VERSION 5.7 ;
BUSBITCHARS "[]" ;
DIVIDERCHAR "/" ;

PROPERTYDEFINITIONS
  MACRO pkpIndependentSourceSHA256 STRING ;
  MACRO CatenaDesignType STRING ;
END PROPERTYDEFINITIONS

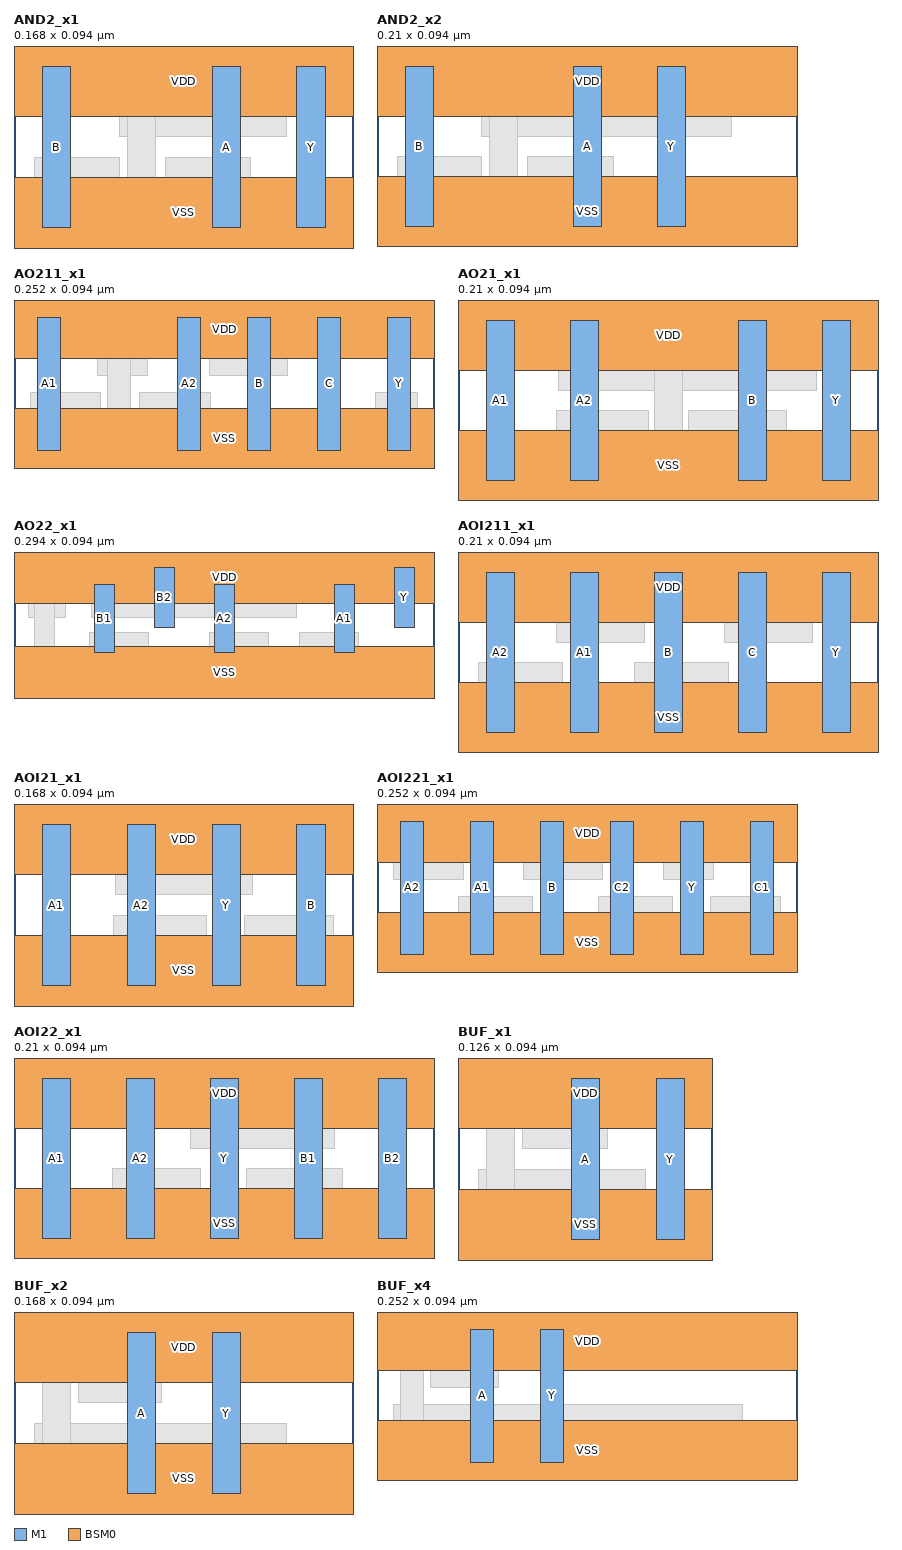
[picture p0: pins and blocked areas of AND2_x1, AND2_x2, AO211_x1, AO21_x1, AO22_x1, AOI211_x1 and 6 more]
MACRO AND2_x1
  CLASS CORE ;
  ORIGIN 0 0 ;
  FOREIGN AND2_x1 0 0 ;
  SIZE 0.168 BY 0.094 ;
  SYMMETRY X Y ;
  SITE CoreSite ;
  PIN A
    DIRECTION INPUT ;
    USE SIGNAL ;
    PORT
      LAYER M1 ;
        RECT 0.098 0.007 0.112 0.087 ;
    END
  END A
  PIN B
    DIRECTION INPUT ;
    USE SIGNAL ;
    PORT
      LAYER M1 ;
        RECT 0.014 0.007 0.028 0.087 ;
    END
  END B
  PIN Y
    DIRECTION OUTPUT ;
    USE SIGNAL ;
    PORT
      LAYER M1 ;
        RECT 0.14 0.007 0.154 0.087 ;
    END
  END Y
  PIN VDD
    DIRECTION INOUT ;
    USE POWER ;
    SHAPE ABUTMENT ;
    PORT
      LAYER BSM0 ;
        RECT 0 0.062 0.168 0.126 ;
    END
  END VDD
  PIN VSS
    DIRECTION INOUT ;
    USE GROUND ;
    SHAPE ABUTMENT ;
    PORT
      LAYER BSM0 ;
        RECT 0 -0.032 0.168 0.032 ;
    END
  END VSS
  OBS
    LAYER M0 ;
      RECT 0.133 0.01 0.158 0.021 ;
      RECT 0.133 0.073 0.158 0.084 ;
      RECT 0.052 0.052 0.135 0.063 ;
      RECT 0.075 0.031 0.117 0.042 ;
      RECT 0.01 0.01 0.08 0.021 ;
      RECT 0.05 0.073 0.08 0.084 ;
      RECT 0.01 0.031 0.052 0.042 ;
    LAYER M1 ;
      RECT 0.056 0.007 0.07 0.087 ;
  END
END AND2_x1

MACRO AND2_x2
  CLASS CORE ;
  ORIGIN 0 0 ;
  FOREIGN AND2_x2 0 0 ;
  SIZE 0.21 BY 0.094 ;
  SYMMETRY X Y ;
  SITE CoreSite ;
  PIN A
    DIRECTION INPUT ;
    USE SIGNAL ;
    PORT
      LAYER M1 ;
        RECT 0.098 0.007 0.112 0.087 ;
    END
  END A
  PIN B
    DIRECTION INPUT ;
    USE SIGNAL ;
    PORT
      LAYER M1 ;
        RECT 0.014 0.007 0.028 0.087 ;
    END
  END B
  PIN Y
    DIRECTION OUTPUT ;
    USE SIGNAL ;
    PORT
      LAYER M1 ;
        RECT 0.14 0.007 0.154 0.087 ;
    END
  END Y
  PIN VDD
    DIRECTION INOUT ;
    USE POWER ;
    SHAPE ABUTMENT ;
    PORT
      LAYER BSM0 ;
        RECT 0 0.062 0.21 0.126 ;
    END
  END VDD
  PIN VSS
    DIRECTION INOUT ;
    USE GROUND ;
    SHAPE ABUTMENT ;
    PORT
      LAYER BSM0 ;
        RECT 0 -0.032 0.21 0.032 ;
    END
  END VSS
  OBS
    LAYER M0 ;
      RECT 0.052 0.052 0.177 0.063 ;
      RECT 0.134 0.01 0.164 0.021 ;
      RECT 0.134 0.073 0.164 0.084 ;
      RECT 0.075 0.031 0.118 0.042 ;
      RECT 0.01 0.01 0.08 0.021 ;
      RECT 0.05 0.073 0.08 0.084 ;
      RECT 0.01 0.031 0.052 0.042 ;
    LAYER M1 ;
      RECT 0.056 0.007 0.07 0.087 ;
  END
END AND2_x2

MACRO AO211_x1
  CLASS CORE ;
  ORIGIN 0 0 ;
  FOREIGN AO211_x1 0 0 ;
  SIZE 0.252 BY 0.094 ;
  SYMMETRY X Y ;
  SITE CoreSite ;
  PIN A1
    DIRECTION INPUT ;
    USE SIGNAL ;
    PORT
      LAYER M1 ;
        RECT 0.014 0.007 0.028 0.087 ;
    END
  END A1
  PIN A2
    DIRECTION INPUT ;
    USE SIGNAL ;
    PORT
      LAYER M1 ;
        RECT 0.098 0.007 0.112 0.087 ;
    END
  END A2
  PIN B
    DIRECTION INPUT ;
    USE SIGNAL ;
    PORT
      LAYER M1 ;
        RECT 0.14 0.007 0.154 0.087 ;
    END
  END B
  PIN C
    DIRECTION INPUT ;
    USE SIGNAL ;
    PORT
      LAYER M1 ;
        RECT 0.182 0.007 0.196 0.087 ;
    END
  END C
  PIN Y
    DIRECTION OUTPUT ;
    USE SIGNAL ;
    PORT
      LAYER M1 ;
        RECT 0.224 0.007 0.238 0.087 ;
    END
  END Y
  PIN VDD
    DIRECTION INOUT ;
    USE POWER ;
    SHAPE ABUTMENT ;
    PORT
      LAYER BSM0 ;
        RECT 0 0.062 0.252 0.126 ;
    END
  END VDD
  PIN VSS
    DIRECTION INOUT ;
    USE GROUND ;
    SHAPE ABUTMENT ;
    PORT
      LAYER BSM0 ;
        RECT 0 -0.032 0.252 0.032 ;
    END
  END VSS
  OBS
    LAYER M0 ;
      RECT 0.217 0.031 0.242 0.042 ;
      RECT 0.217 0.073 0.242 0.084 ;
      RECT 0.01 0.01 0.219 0.021 ;
      RECT 0.159 0.073 0.199 0.084 ;
      RECT 0.117 0.052 0.164 0.063 ;
      RECT 0.075 0.031 0.118 0.042 ;
      RECT 0.012 0.073 0.114 0.084 ;
      RECT 0.05 0.052 0.08 0.063 ;
      RECT 0.01 0.031 0.052 0.042 ;
    LAYER M1 ;
      RECT 0.056 0.007 0.07 0.087 ;
  END
END AO211_x1

MACRO AO21_x1
  CLASS CORE ;
  ORIGIN 0 0 ;
  FOREIGN AO21_x1 0 0 ;
  SIZE 0.21 BY 0.094 ;
  SYMMETRY X Y ;
  SITE CoreSite ;
  PIN A1
    DIRECTION INPUT ;
    USE SIGNAL ;
    PORT
      LAYER M1 ;
        RECT 0.014 0.007 0.028 0.087 ;
    END
  END A1
  PIN A2
    DIRECTION INPUT ;
    USE SIGNAL ;
    PORT
      LAYER M1 ;
        RECT 0.056 0.007 0.07 0.087 ;
    END
  END A2
  PIN B
    DIRECTION INPUT ;
    USE SIGNAL ;
    PORT
      LAYER M1 ;
        RECT 0.14 0.007 0.154 0.087 ;
    END
  END B
  PIN Y
    DIRECTION OUTPUT ;
    USE SIGNAL ;
    PORT
      LAYER M1 ;
        RECT 0.182 0.007 0.196 0.087 ;
    END
  END Y
  PIN VDD
    DIRECTION INOUT ;
    USE POWER ;
    SHAPE ABUTMENT ;
    PORT
      LAYER BSM0 ;
        RECT 0 0.062 0.21 0.126 ;
    END
  END VDD
  PIN VSS
    DIRECTION INOUT ;
    USE GROUND ;
    SHAPE ABUTMENT ;
    PORT
      LAYER BSM0 ;
        RECT 0 -0.032 0.21 0.032 ;
    END
  END VSS
  OBS
    LAYER M0 ;
      RECT 0.172 0.01 0.2 0.021 ;
      RECT 0.172 0.073 0.2 0.084 ;
      RECT 0.05 0.052 0.179 0.063 ;
      RECT 0.115 0.031 0.164 0.042 ;
      RECT 0.088 0.01 0.119 0.021 ;
      RECT 0.01 0.073 0.117 0.084 ;
      RECT 0.049 0.031 0.095 0.042 ;
      RECT 0.01 0.01 0.053 0.021 ;
    LAYER M1 ;
      RECT 0.098 0.007 0.112 0.087 ;
  END
END AO21_x1

MACRO AO22_x1
  CLASS CORE ;
  ORIGIN 0 0 ;
  FOREIGN AO22_x1 0 0 ;
  SIZE 0.294 BY 0.094 ;
  SYMMETRY X Y ;
  SITE CoreSite ;
  PIN A1
    DIRECTION INPUT ;
    USE SIGNAL ;
    PORT
      LAYER M1 ;
        RECT 0.224 0.028 0.238 0.0755 ;
    END
  END A1
  PIN A2
    DIRECTION INPUT ;
    USE SIGNAL ;
    PORT
      LAYER M1 ;
        RECT 0.14 0.028 0.154 0.0755 ;
    END
  END A2
  PIN B1
    DIRECTION INPUT ;
    USE SIGNAL ;
    PORT
      LAYER M1 ;
        RECT 0.056 0.028 0.07 0.0755 ;
    END
  END B1
  PIN B2
    DIRECTION INPUT ;
    USE SIGNAL ;
    PORT
      LAYER M1 ;
        RECT 0.098 0.045 0.112 0.087 ;
    END
  END B2
  PIN Y
    DIRECTION OUTPUT ;
    USE SIGNAL ;
    PORT
      LAYER M1 ;
        RECT 0.266 0.045 0.28 0.087 ;
    END
  END Y
  PIN VDD
    DIRECTION INOUT ;
    USE POWER ;
    SHAPE ABUTMENT ;
    PORT
      LAYER BSM0 ;
        RECT 0 0.062 0.294 0.126 ;
    END
  END VDD
  PIN VSS
    DIRECTION INOUT ;
    USE GROUND ;
    SHAPE ABUTMENT ;
    PORT
      LAYER BSM0 ;
        RECT 0 -0.032 0.294 0.032 ;
    END
  END VSS
  OBS
    LAYER M0 ;
      RECT 0.256 0.073 0.284 0.084 ;
      RECT 0.01 0.01 0.262 0.021 ;
      RECT 0.2 0.031 0.241 0.042 ;
      RECT 0.054 0.052 0.198 0.063 ;
      RECT 0.137 0.031 0.178 0.042 ;
      RECT 0.032 0.073 0.115 0.084 ;
      RECT 0.053 0.031 0.094 0.042 ;
      RECT 0.01 0.052 0.036 0.063 ;
    LAYER M1 ;
      RECT 0.014 0.007 0.028 0.076 ;
  END
  PROPERTY pkpIndependentSourceSHA256 "be00ef7e564fc46890b79b18678042070a181a3fd22f0e1ad2fda87f76c24992" ;
END AO22_x1

MACRO AOI211_x1
  CLASS CORE ;
  ORIGIN 0 0 ;
  FOREIGN AOI211_x1 0 0 ;
  SIZE 0.21 BY 0.094 ;
  SYMMETRY X Y ;
  SITE CoreSite ;
  PIN A1
    DIRECTION INPUT ;
    USE SIGNAL ;
    PORT
      LAYER M1 ;
        RECT 0.056 0.007 0.07 0.087 ;
    END
  END A1
  PIN A2
    DIRECTION INPUT ;
    USE SIGNAL ;
    PORT
      LAYER M1 ;
        RECT 0.014 0.007 0.028 0.087 ;
    END
  END A2
  PIN B
    DIRECTION INPUT ;
    USE SIGNAL ;
    PORT
      LAYER M1 ;
        RECT 0.098 0.007 0.112 0.087 ;
    END
  END B
  PIN C
    DIRECTION INPUT ;
    USE SIGNAL ;
    PORT
      LAYER M1 ;
        RECT 0.14 0.007 0.154 0.087 ;
    END
  END C
  PIN Y
    DIRECTION OUTPUT ;
    USE SIGNAL ;
    PORT
      LAYER M1 ;
        RECT 0.182 0.007 0.196 0.087 ;
    END
  END Y
  PIN VDD
    DIRECTION INOUT ;
    USE POWER ;
    SHAPE ABUTMENT ;
    PORT
      LAYER BSM0 ;
        RECT 0 0.062 0.21 0.126 ;
    END
  END VDD
  PIN VSS
    DIRECTION INOUT ;
    USE GROUND ;
    SHAPE ABUTMENT ;
    PORT
      LAYER BSM0 ;
        RECT 0 -0.032 0.21 0.032 ;
    END
  END VSS
  OBS
    LAYER M0 ;
      RECT 0.096 0.01 0.2 0.021 ;
      RECT 0.172 0.073 0.2 0.084 ;
      RECT 0.133 0.052 0.177 0.063 ;
      RECT 0.088 0.031 0.135 0.042 ;
      RECT 0.012 0.073 0.114 0.084 ;
      RECT 0.049 0.052 0.093 0.063 ;
      RECT 0.01 0.031 0.052 0.042 ;
  END
END AOI211_x1

MACRO AOI21_x1
  CLASS CORE ;
  ORIGIN 0 0 ;
  FOREIGN AOI21_x1 0 0 ;
  SIZE 0.168 BY 0.094 ;
  SYMMETRY X Y ;
  SITE CoreSite ;
  PIN A1
    DIRECTION INPUT ;
    USE SIGNAL ;
    PORT
      LAYER M1 ;
        RECT 0.014 0.007 0.028 0.087 ;
    END
  END A1
  PIN A2
    DIRECTION INPUT ;
    USE SIGNAL ;
    PORT
      LAYER M1 ;
        RECT 0.056 0.007 0.07 0.087 ;
    END
  END A2
  PIN B
    DIRECTION INPUT ;
    USE SIGNAL ;
    PORT
      LAYER M1 ;
        RECT 0.14 0.007 0.154 0.087 ;
    END
  END B
  PIN Y
    DIRECTION OUTPUT ;
    USE SIGNAL ;
    PORT
      LAYER M1 ;
        RECT 0.098 0.007 0.112 0.087 ;
    END
  END Y
  PIN VDD
    DIRECTION INOUT ;
    USE POWER ;
    SHAPE ABUTMENT ;
    PORT
      LAYER BSM0 ;
        RECT 0 0.062 0.168 0.126 ;
    END
  END VDD
  PIN VSS
    DIRECTION INOUT ;
    USE GROUND ;
    SHAPE ABUTMENT ;
    PORT
      LAYER BSM0 ;
        RECT 0 -0.032 0.168 0.032 ;
    END
  END VSS
  OBS
    LAYER M0 ;
      RECT 0.114 0.031 0.158 0.042 ;
      RECT 0.088 0.01 0.118 0.021 ;
      RECT 0.05 0.052 0.118 0.063 ;
      RECT 0.01 0.073 0.118 0.084 ;
      RECT 0.049 0.031 0.095 0.042 ;
      RECT 0.01 0.01 0.052 0.021 ;
  END
END AOI21_x1

MACRO AOI221_x1
  CLASS CORE ;
  ORIGIN 0 0 ;
  FOREIGN AOI221_x1 0 0 ;
  SIZE 0.252 BY 0.094 ;
  SYMMETRY X Y ;
  SITE CoreSite ;
  PIN A1
    DIRECTION INPUT ;
    USE SIGNAL ;
    PORT
      LAYER M1 ;
        RECT 0.056 0.007 0.07 0.087 ;
    END
  END A1
  PIN A2
    DIRECTION INPUT ;
    USE SIGNAL ;
    PORT
      LAYER M1 ;
        RECT 0.014 0.007 0.028 0.087 ;
    END
  END A2
  PIN B
    DIRECTION INPUT ;
    USE SIGNAL ;
    PORT
      LAYER M1 ;
        RECT 0.098 0.007 0.112 0.087 ;
    END
  END B
  PIN C1
    DIRECTION INPUT ;
    USE SIGNAL ;
    PORT
      LAYER M1 ;
        RECT 0.224 0.007 0.238 0.087 ;
    END
  END C1
  PIN C2
    DIRECTION INPUT ;
    USE SIGNAL ;
    PORT
      LAYER M1 ;
        RECT 0.14 0.007 0.154 0.087 ;
    END
  END C2
  PIN Y
    DIRECTION OUTPUT ;
    USE SIGNAL ;
    PORT
      LAYER M1 ;
        RECT 0.182 0.007 0.196 0.087 ;
    END
  END Y
  PIN VDD
    DIRECTION INOUT ;
    USE POWER ;
    SHAPE ABUTMENT ;
    PORT
      LAYER BSM0 ;
        RECT 0 0.062 0.252 0.126 ;
    END
  END VDD
  PIN VSS
    DIRECTION INOUT ;
    USE GROUND ;
    SHAPE ABUTMENT ;
    PORT
      LAYER BSM0 ;
        RECT 0 -0.032 0.252 0.032 ;
    END
  END VSS
  OBS
    LAYER M0 ;
      RECT 0.2 0.031 0.242 0.042 ;
      RECT 0.096 0.01 0.24 0.021 ;
      RECT 0.138 0.073 0.24 0.084 ;
      RECT 0.172 0.052 0.202 0.063 ;
      RECT 0.133 0.031 0.177 0.042 ;
      RECT 0.088 0.052 0.135 0.063 ;
      RECT 0.012 0.073 0.114 0.084 ;
      RECT 0.049 0.031 0.093 0.042 ;
      RECT 0.01 0.052 0.052 0.063 ;
  END
END AOI221_x1

MACRO AOI22_x1
  CLASS CORE ;
  ORIGIN 0 0 ;
  FOREIGN AOI22_x1 0 0 ;
  SIZE 0.21 BY 0.094 ;
  SYMMETRY X Y ;
  SITE CoreSite ;
  PIN A1
    DIRECTION INPUT ;
    USE SIGNAL ;
    PORT
      LAYER M1 ;
        RECT 0.014 0.007 0.028 0.087 ;
    END
  END A1
  PIN A2
    DIRECTION INPUT ;
    USE SIGNAL ;
    PORT
      LAYER M1 ;
        RECT 0.056 0.007 0.07 0.087 ;
    END
  END A2
  PIN B1
    DIRECTION INPUT ;
    USE SIGNAL ;
    PORT
      LAYER M1 ;
        RECT 0.14 0.007 0.154 0.087 ;
    END
  END B1
  PIN B2
    DIRECTION INPUT ;
    USE SIGNAL ;
    PORT
      LAYER M1 ;
        RECT 0.182 0.007 0.196 0.087 ;
    END
  END B2
  PIN Y
    DIRECTION OUTPUT ;
    USE SIGNAL ;
    PORT
      LAYER M1 ;
        RECT 0.098 0.007 0.112 0.087 ;
    END
  END Y
  PIN VDD
    DIRECTION INOUT ;
    USE POWER ;
    SHAPE ABUTMENT ;
    PORT
      LAYER BSM0 ;
        RECT 0 0.062 0.21 0.126 ;
    END
  END VDD
  PIN VSS
    DIRECTION INOUT ;
    USE GROUND ;
    SHAPE ABUTMENT ;
    PORT
      LAYER BSM0 ;
        RECT 0 -0.032 0.21 0.032 ;
    END
  END VSS
  OBS
    LAYER M0 ;
      RECT 0.156 0.01 0.2 0.021 ;
      RECT 0.01 0.073 0.2 0.084 ;
      RECT 0.116 0.031 0.164 0.042 ;
      RECT 0.088 0.052 0.16 0.063 ;
      RECT 0.088 0.01 0.119 0.021 ;
      RECT 0.049 0.031 0.093 0.042 ;
      RECT 0.011 0.01 0.052 0.021 ;
  END
  PROPERTY CatenaDesignType "deviceLevel" ;
END AOI22_x1

MACRO BUF_x1
  CLASS CORE ;
  ORIGIN 0 0 ;
  FOREIGN BUF_x1 0 0 ;
  SIZE 0.126 BY 0.094 ;
  SYMMETRY X Y ;
  SITE CoreSite ;
  PIN A
    DIRECTION INPUT ;
    USE SIGNAL ;
    PORT
      LAYER M1 ;
        RECT 0.056 0.007 0.07 0.087 ;
    END
  END A
  PIN Y
    DIRECTION OUTPUT ;
    USE SIGNAL ;
    PORT
      LAYER M1 ;
        RECT 0.098 0.007 0.112 0.087 ;
    END
  END Y
  PIN VDD
    DIRECTION INOUT ;
    USE POWER ;
    SHAPE ABUTMENT ;
    PORT
      LAYER BSM0 ;
        RECT 0 0.062 0.126 0.126 ;
    END
  END VDD
  PIN VSS
    DIRECTION INOUT ;
    USE GROUND ;
    SHAPE ABUTMENT ;
    PORT
      LAYER BSM0 ;
        RECT 0 -0.032 0.126 0.032 ;
    END
  END VSS
  OBS
    LAYER M0 ;
      RECT 0.088 0.01 0.116 0.021 ;
      RECT 0.088 0.073 0.116 0.084 ;
      RECT 0.01 0.031 0.093 0.042 ;
      RECT 0.032 0.052 0.074 0.063 ;
      RECT 0.01 0.01 0.035 0.021 ;
      RECT 0.01 0.073 0.035 0.084 ;
    LAYER M1 ;
      RECT 0.014 0.007 0.028 0.087 ;
  END
END BUF_x1

MACRO BUF_x2
  CLASS CORE ;
  ORIGIN 0 0 ;
  FOREIGN BUF_x2 0 0 ;
  SIZE 0.168 BY 0.094 ;
  SYMMETRY X Y ;
  SITE CoreSite ;
  PIN A
    DIRECTION INPUT ;
    USE SIGNAL ;
    PORT
      LAYER M1 ;
        RECT 0.056 0.007 0.07 0.087 ;
    END
  END A
  PIN Y
    DIRECTION OUTPUT ;
    USE SIGNAL ;
    PORT
      LAYER M1 ;
        RECT 0.098 0.007 0.112 0.087 ;
    END
  END Y
  PIN VDD
    DIRECTION INOUT ;
    USE POWER ;
    SHAPE ABUTMENT ;
    PORT
      LAYER BSM0 ;
        RECT 0 0.062 0.168 0.126 ;
    END
  END VDD
  PIN VSS
    DIRECTION INOUT ;
    USE GROUND ;
    SHAPE ABUTMENT ;
    PORT
      LAYER BSM0 ;
        RECT 0 -0.032 0.168 0.032 ;
    END
  END VSS
  OBS
    LAYER M0 ;
      RECT 0.01 0.031 0.135 0.042 ;
      RECT 0.088 0.01 0.118 0.021 ;
      RECT 0.088 0.073 0.118 0.084 ;
      RECT 0.032 0.052 0.073 0.063 ;
      RECT 0.01 0.01 0.035 0.021 ;
      RECT 0.01 0.073 0.035 0.084 ;
    LAYER M1 ;
      RECT 0.014 0.007 0.028 0.087 ;
  END
END BUF_x2

MACRO BUF_x4
  CLASS CORE ;
  ORIGIN 0 0 ;
  FOREIGN BUF_x4 0 0 ;
  SIZE 0.252 BY 0.094 ;
  SYMMETRY X Y ;
  SITE CoreSite ;
  PIN A
    DIRECTION INPUT ;
    USE SIGNAL ;
    PORT
      LAYER M1 ;
        RECT 0.056 0.007 0.07 0.087 ;
    END
  END A
  PIN Y
    DIRECTION OUTPUT ;
    USE SIGNAL ;
    PORT
      LAYER M1 ;
        RECT 0.098 0.007 0.112 0.087 ;
    END
  END Y
  PIN VDD
    DIRECTION INOUT ;
    USE POWER ;
    SHAPE ABUTMENT ;
    PORT
      LAYER BSM0 ;
        RECT 0 0.062 0.252 0.126 ;
    END
  END VDD
  PIN VSS
    DIRECTION INOUT ;
    USE GROUND ;
    SHAPE ABUTMENT ;
    PORT
      LAYER BSM0 ;
        RECT 0 -0.032 0.252 0.032 ;
    END
  END VSS
  OBS
    LAYER M0 ;
      RECT 0.01 0.031 0.219 0.042 ;
      RECT 0.092 0.01 0.199 0.021 ;
      RECT 0.092 0.073 0.199 0.084 ;
      RECT 0.032 0.052 0.073 0.063 ;
      RECT 0.01 0.01 0.035 0.021 ;
      RECT 0.01 0.073 0.035 0.084 ;
    LAYER M1 ;
      RECT 0.014 0.007 0.028 0.087 ;
  END
END BUF_x4

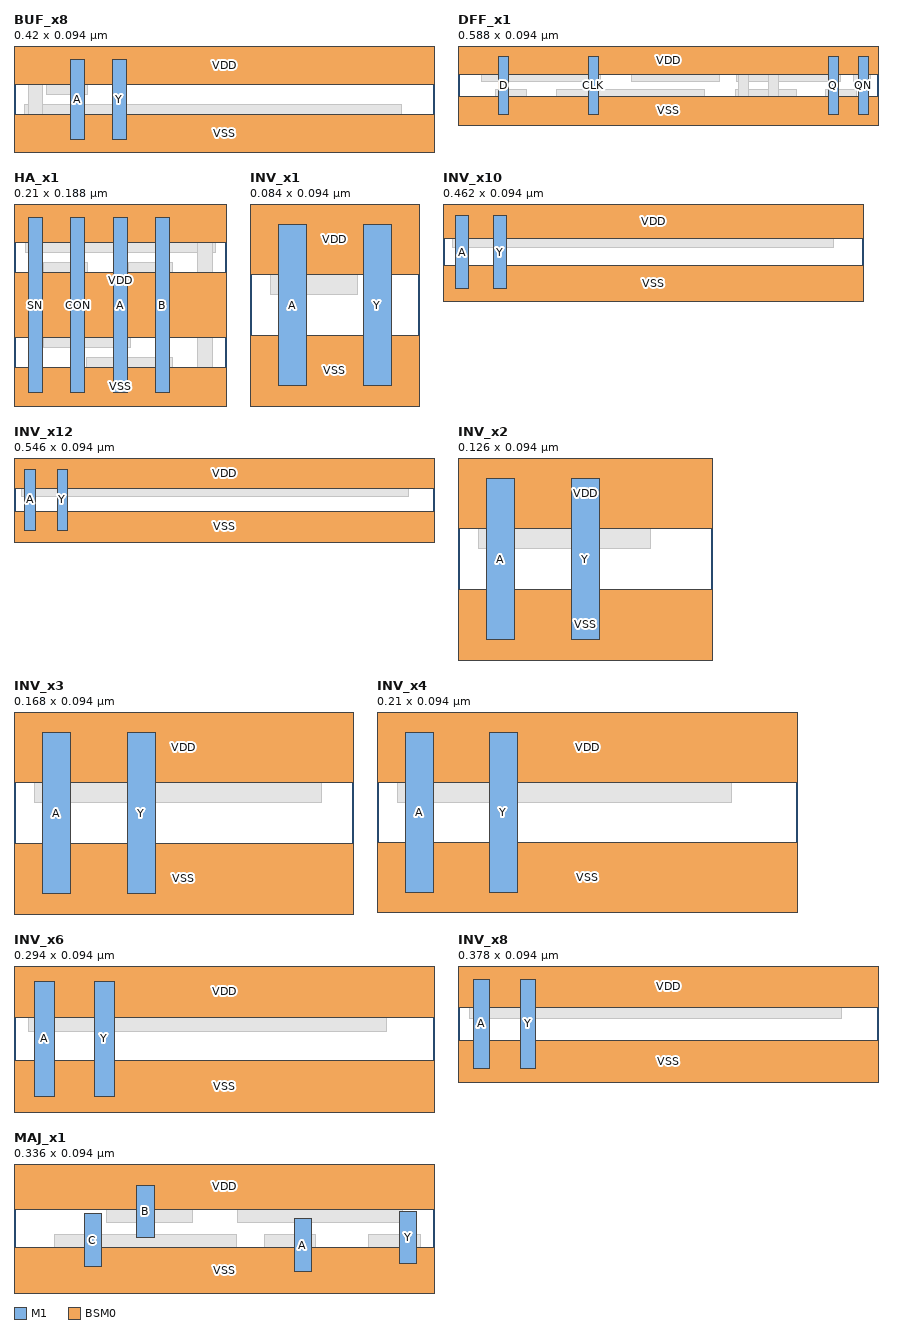
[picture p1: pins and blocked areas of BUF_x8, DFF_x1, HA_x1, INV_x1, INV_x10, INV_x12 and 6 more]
MACRO BUF_x8
  CLASS CORE ;
  ORIGIN 0 0 ;
  FOREIGN BUF_x8 0 0 ;
  SIZE 0.42 BY 0.094 ;
  SYMMETRY X Y ;
  SITE CoreSite ;
  PIN A
    DIRECTION INPUT ;
    USE SIGNAL ;
    PORT
      LAYER M1 ;
        RECT 0.056 0.007 0.07 0.087 ;
    END
  END A
  PIN Y
    DIRECTION OUTPUT ;
    USE SIGNAL ;
    PORT
      LAYER M1 ;
        RECT 0.098 0.007 0.112 0.087 ;
    END
  END Y
  PIN VDD
    DIRECTION INOUT ;
    USE POWER ;
    SHAPE ABUTMENT ;
    PORT
      LAYER BSM0 ;
        RECT 0 0.062 0.42 0.126 ;
    END
  END VDD
  PIN VSS
    DIRECTION INOUT ;
    USE GROUND ;
    SHAPE ABUTMENT ;
    PORT
      LAYER BSM0 ;
        RECT 0 -0.032 0.42 0.032 ;
    END
  END VSS
  OBS
    LAYER M0 ;
      RECT 0.01 0.031 0.387 0.042 ;
      RECT 0.092 0.01 0.367 0.021 ;
      RECT 0.092 0.073 0.367 0.084 ;
      RECT 0.032 0.052 0.073 0.063 ;
      RECT 0.01 0.01 0.035 0.021 ;
      RECT 0.01 0.073 0.035 0.084 ;
    LAYER M1 ;
      RECT 0.014 0.007 0.028 0.087 ;
  END
END BUF_x8

MACRO DFF_x1
  CLASS CORE ;
  ORIGIN 0 0 ;
  FOREIGN DFF_x1 0 0 ;
  SIZE 0.588 BY 0.094 ;
  SYMMETRY X Y ;
  SITE CoreSite ;
  PIN CLK
    DIRECTION INPUT ;
    USE CLOCK ;
    PORT
      LAYER M1 ;
        RECT 0.182 0.007 0.196 0.087 ;
    END
  END CLK
  PIN D
    DIRECTION INPUT ;
    USE SIGNAL ;
    PORT
      LAYER M1 ;
        RECT 0.056 0.007 0.07 0.087 ;
    END
  END D
  PIN Q
    DIRECTION OUTPUT ;
    USE SIGNAL ;
    PORT
      LAYER M1 ;
        RECT 0.518 0.007 0.532 0.087 ;
    END
  END Q
  PIN QN
    DIRECTION OUTPUT ;
    USE SIGNAL ;
    PORT
      LAYER M1 ;
        RECT 0.56 0.007 0.574 0.087 ;
    END
  END QN
  PIN VDD
    DIRECTION INOUT ;
    USE POWER ;
    SHAPE ABUTMENT ;
    PORT
      LAYER BSM0 ;
        RECT 0 0.062 0.588 0.126 ;
    END
  END VDD
  PIN VSS
    DIRECTION INOUT ;
    USE GROUND ;
    SHAPE ABUTMENT ;
    PORT
      LAYER BSM0 ;
        RECT 0 -0.032 0.588 0.032 ;
    END
  END VSS
  OBS
    LAYER M0 ;
      RECT 0.553 0.052 0.578 0.063 ;
      RECT 0.495 0.01 0.577 0.021 ;
      RECT 0.515 0.031 0.5585 0.042 ;
      RECT 0.39 0.052 0.535 0.063 ;
      RECT 0.389 0.031 0.4745 0.042 ;
      RECT 0.431 0.073 0.4745 0.084 ;
      RECT 0.179 0.01 0.451 0.021 ;
      RECT 0.012 0.073 0.409 0.084 ;
      RECT 0.243 0.052 0.366 0.063 ;
      RECT 0.138 0.031 0.345 0.042 ;
      RECT 0.033 0.052 0.199 0.063 ;
      RECT 0.012 0.01 0.135 0.021 ;
      RECT 0.053 0.031 0.0965 0.042 ;
    LAYER M1 ;
      RECT 0.434 0.007 0.448 0.087 ;
      RECT 0.392 0.007 0.406 0.087 ;
  END
END DFF_x1

MACRO HA_x1
  CLASS CORE ;
  ORIGIN 0 0 ;
  FOREIGN HA_x1 0 0 ;
  SIZE 0.21 BY 0.188 ;
  SYMMETRY X Y ;
  SITE CoreSite ;
  PIN A
    DIRECTION INPUT ;
    USE SIGNAL ;
    PORT
      LAYER M1 ;
        RECT 0.098 0.007 0.112 0.181 ;
    END
  END A
  PIN B
    DIRECTION INPUT ;
    USE SIGNAL ;
    PORT
      LAYER M1 ;
        RECT 0.14 0.007 0.154 0.181 ;
    END
  END B
  PIN CON
    DIRECTION OUTPUT ;
    USE SIGNAL ;
    PORT
      LAYER M1 ;
        RECT 0.056 0.007 0.07 0.181 ;
    END
  END CON
  PIN SN
    DIRECTION OUTPUT ;
    USE SIGNAL ;
    PORT
      LAYER M1 ;
        RECT 0.014 0.007 0.028 0.181 ;
    END
  END SN
  PIN VDD
    DIRECTION INOUT ;
    USE POWER ;
    SHAPE ABUTMENT ;
    PORT
      LAYER BSM0 ;
        RECT 0 0.062 0.21 0.126 ;
    END
  END VDD
  PIN VSS
    DIRECTION INOUT ;
    USE GROUND ;
    SHAPE ABUTMENT ;
    PORT
      LAYER BSM0 ;
        RECT 0 -0.032 0.21 0.032 ;
        RECT 0 0.156 0.21 0.22 ;
    END
  END VSS
  OBS
    LAYER M0 ;
      RECT 0.1345 0.104 0.199 0.115 ;
      RECT 0.011 0.146 0.199 0.157 ;
      RECT 0.0715 0.031 0.157 0.042 ;
      RECT 0.1135 0.125 0.157 0.136 ;
      RECT 0.054 0.167 0.156 0.178 ;
      RECT 0.053 0.01 0.1175 0.021 ;
      RECT 0.0295 0.052 0.115 0.063 ;
      RECT 0.0715 0.104 0.115 0.115 ;
      RECT 0.012 0.073 0.114 0.084 ;
      RECT 0.0295 0.125 0.073 0.136 ;
      RECT 0.01 0.104 0.035 0.115 ;
    LAYER M1 ;
      RECT 0.182 0.007 0.196 0.181 ;
  END
END HA_x1

MACRO INV_x1
  CLASS CORE ;
  ORIGIN 0 0 ;
  FOREIGN INV_x1 0 0 ;
  SIZE 0.084 BY 0.094 ;
  SYMMETRY X Y ;
  SITE CoreSite ;
  PIN A
    DIRECTION INPUT ;
    USE SIGNAL ;
    PORT
      LAYER M1 ;
        RECT 0.014 0.007 0.028 0.087 ;
    END
  END A
  PIN Y
    DIRECTION OUTPUT ;
    USE SIGNAL ;
    PORT
      LAYER M1 ;
        RECT 0.056 0.007 0.07 0.087 ;
    END
  END Y
  PIN VDD
    DIRECTION INOUT ;
    USE POWER ;
    SHAPE ABUTMENT ;
    PORT
      LAYER BSM0 ;
        RECT 0 0.062 0.084 0.126 ;
    END
  END VDD
  PIN VSS
    DIRECTION INOUT ;
    USE GROUND ;
    SHAPE ABUTMENT ;
    PORT
      LAYER BSM0 ;
        RECT 0 -0.032 0.084 0.032 ;
    END
  END VSS
  OBS
    LAYER M0 ;
      RECT 0.032 0.01 0.074 0.021 ;
      RECT 0.032 0.073 0.074 0.084 ;
      RECT 0.01 0.052 0.053 0.063 ;
  END
END INV_x1

MACRO INV_x10
  CLASS CORE ;
  ORIGIN 0 0 ;
  FOREIGN INV_x10 0 0 ;
  SIZE 0.462 BY 0.094 ;
  SYMMETRY X Y ;
  SITE CoreSite ;
  PIN A
    DIRECTION INPUT ;
    USE SIGNAL ;
    PORT
      LAYER M1 ;
        RECT 0.014 0.007 0.028 0.087 ;
    END
  END A
  PIN Y
    DIRECTION OUTPUT ;
    USE SIGNAL ;
    PORT
      LAYER M1 ;
        RECT 0.056 0.007 0.07 0.087 ;
    END
  END Y
  PIN VDD
    DIRECTION INOUT ;
    USE POWER ;
    SHAPE ABUTMENT ;
    PORT
      LAYER BSM0 ;
        RECT 0 0.062 0.462 0.126 ;
    END
  END VDD
  PIN VSS
    DIRECTION INOUT ;
    USE GROUND ;
    SHAPE ABUTMENT ;
    PORT
      LAYER BSM0 ;
        RECT 0 -0.032 0.462 0.032 ;
    END
  END VSS
  OBS
    LAYER M0 ;
      RECT 0.01 0.052 0.429 0.063 ;
      RECT 0.05 0.01 0.41 0.021 ;
      RECT 0.05 0.073 0.409 0.084 ;
  END
END INV_x10

MACRO INV_x12
  CLASS CORE ;
  ORIGIN 0 0 ;
  FOREIGN INV_x12 0 0 ;
  SIZE 0.546 BY 0.094 ;
  SYMMETRY X Y ;
  SITE CoreSite ;
  PIN A
    DIRECTION INPUT ;
    USE SIGNAL ;
    PORT
      LAYER M1 ;
        RECT 0.014 0.007 0.028 0.087 ;
    END
  END A
  PIN Y
    DIRECTION OUTPUT ;
    USE SIGNAL ;
    PORT
      LAYER M1 ;
        RECT 0.056 0.007 0.07 0.087 ;
    END
  END Y
  PIN VDD
    DIRECTION INOUT ;
    USE POWER ;
    SHAPE ABUTMENT ;
    PORT
      LAYER BSM0 ;
        RECT 0 0.062 0.546 0.126 ;
    END
  END VDD
  PIN VSS
    DIRECTION INOUT ;
    USE GROUND ;
    SHAPE ABUTMENT ;
    PORT
      LAYER BSM0 ;
        RECT 0 -0.032 0.546 0.032 ;
    END
  END VSS
  OBS
    LAYER M0 ;
      RECT 0.01 0.052 0.513 0.063 ;
      RECT 0.05 0.01 0.493 0.021 ;
      RECT 0.05 0.073 0.493 0.084 ;
  END
END INV_x12

MACRO INV_x2
  CLASS CORE ;
  ORIGIN 0 0 ;
  FOREIGN INV_x2 0 0 ;
  SIZE 0.126 BY 0.094 ;
  SYMMETRY X Y ;
  SITE CoreSite ;
  PIN A
    DIRECTION INPUT ;
    USE SIGNAL ;
    PORT
      LAYER M1 ;
        RECT 0.014 0.007 0.028 0.087 ;
    END
  END A
  PIN Y
    DIRECTION OUTPUT ;
    USE SIGNAL ;
    PORT
      LAYER M1 ;
        RECT 0.056 0.007 0.07 0.087 ;
    END
  END Y
  PIN VDD
    DIRECTION INOUT ;
    USE POWER ;
    SHAPE ABUTMENT ;
    PORT
      LAYER BSM0 ;
        RECT 0 0.062 0.126 0.126 ;
    END
  END VDD
  PIN VSS
    DIRECTION INOUT ;
    USE GROUND ;
    SHAPE ABUTMENT ;
    PORT
      LAYER BSM0 ;
        RECT 0 -0.032 0.126 0.032 ;
    END
  END VSS
  OBS
    LAYER M0 ;
      RECT 0.01 0.052 0.095 0.063 ;
      RECT 0.05 0.01 0.08 0.021 ;
      RECT 0.05 0.073 0.08 0.084 ;
  END
END INV_x2

MACRO INV_x3
  CLASS CORE ;
  ORIGIN 0 0 ;
  FOREIGN INV_x3 0 0 ;
  SIZE 0.168 BY 0.094 ;
  SYMMETRY X Y ;
  SITE CoreSite ;
  PIN A
    DIRECTION INPUT ;
    USE SIGNAL ;
    PORT
      LAYER M1 ;
        RECT 0.014 0.007 0.028 0.087 ;
    END
  END A
  PIN Y
    DIRECTION OUTPUT ;
    USE SIGNAL ;
    PORT
      LAYER M1 ;
        RECT 0.056 0.007 0.07 0.087 ;
    END
  END Y
  PIN VDD
    DIRECTION INOUT ;
    USE POWER ;
    SHAPE ABUTMENT ;
    PORT
      LAYER BSM0 ;
        RECT 0 0.062 0.168 0.126 ;
    END
  END VDD
  PIN VSS
    DIRECTION INOUT ;
    USE GROUND ;
    SHAPE ABUTMENT ;
    PORT
      LAYER BSM0 ;
        RECT 0 -0.032 0.168 0.032 ;
    END
  END VSS
  OBS
    LAYER M0 ;
      RECT 0.05 0.01 0.157 0.021 ;
      RECT 0.05 0.073 0.157 0.084 ;
      RECT 0.01 0.052 0.152 0.063 ;
  END
END INV_x3

MACRO INV_x4
  CLASS CORE ;
  ORIGIN 0 0 ;
  FOREIGN INV_x4 0 0 ;
  SIZE 0.21 BY 0.094 ;
  SYMMETRY X Y ;
  SITE CoreSite ;
  PIN A
    DIRECTION INPUT ;
    USE SIGNAL ;
    PORT
      LAYER M1 ;
        RECT 0.014 0.007 0.028 0.087 ;
    END
  END A
  PIN Y
    DIRECTION OUTPUT ;
    USE SIGNAL ;
    PORT
      LAYER M1 ;
        RECT 0.056 0.007 0.07 0.087 ;
    END
  END Y
  PIN VDD
    DIRECTION INOUT ;
    USE POWER ;
    SHAPE ABUTMENT ;
    PORT
      LAYER BSM0 ;
        RECT 0 0.062 0.21 0.126 ;
    END
  END VDD
  PIN VSS
    DIRECTION INOUT ;
    USE GROUND ;
    SHAPE ABUTMENT ;
    PORT
      LAYER BSM0 ;
        RECT 0 -0.032 0.21 0.032 ;
    END
  END VSS
  OBS
    LAYER M0 ;
      RECT 0.01 0.052 0.177 0.063 ;
      RECT 0.05 0.01 0.157 0.021 ;
      RECT 0.05 0.073 0.157 0.084 ;
  END
END INV_x4

MACRO INV_x6
  CLASS CORE ;
  ORIGIN 0 0 ;
  FOREIGN INV_x6 0 0 ;
  SIZE 0.294 BY 0.094 ;
  SYMMETRY X Y ;
  SITE CoreSite ;
  PIN A
    DIRECTION INPUT ;
    USE SIGNAL ;
    PORT
      LAYER M1 ;
        RECT 0.014 0.007 0.028 0.087 ;
    END
  END A
  PIN Y
    DIRECTION OUTPUT ;
    USE SIGNAL ;
    PORT
      LAYER M1 ;
        RECT 0.056 0.007 0.07 0.087 ;
    END
  END Y
  PIN VDD
    DIRECTION INOUT ;
    USE POWER ;
    SHAPE ABUTMENT ;
    PORT
      LAYER BSM0 ;
        RECT 0 0.062 0.294 0.126 ;
    END
  END VDD
  PIN VSS
    DIRECTION INOUT ;
    USE GROUND ;
    SHAPE ABUTMENT ;
    PORT
      LAYER BSM0 ;
        RECT 0 -0.032 0.294 0.032 ;
    END
  END VSS
  OBS
    LAYER M0 ;
      RECT 0.01 0.052 0.261 0.063 ;
      RECT 0.05 0.01 0.241 0.021 ;
      RECT 0.05 0.073 0.241 0.084 ;
  END
END INV_x6

MACRO INV_x8
  CLASS CORE ;
  ORIGIN 0 0 ;
  FOREIGN INV_x8 0 0 ;
  SIZE 0.378 BY 0.094 ;
  SYMMETRY X Y ;
  SITE CoreSite ;
  PIN A
    DIRECTION INPUT ;
    USE SIGNAL ;
    PORT
      LAYER M1 ;
        RECT 0.014 0.007 0.028 0.087 ;
    END
  END A
  PIN Y
    DIRECTION OUTPUT ;
    USE SIGNAL ;
    PORT
      LAYER M1 ;
        RECT 0.056 0.007 0.07 0.087 ;
    END
  END Y
  PIN VDD
    DIRECTION INOUT ;
    USE POWER ;
    SHAPE ABUTMENT ;
    PORT
      LAYER BSM0 ;
        RECT 0 0.062 0.378 0.126 ;
    END
  END VDD
  PIN VSS
    DIRECTION INOUT ;
    USE GROUND ;
    SHAPE ABUTMENT ;
    PORT
      LAYER BSM0 ;
        RECT 0 -0.032 0.378 0.032 ;
    END
  END VSS
  OBS
    LAYER M0 ;
      RECT 0.01 0.052 0.345 0.063 ;
      RECT 0.05 0.01 0.325 0.021 ;
      RECT 0.05 0.073 0.325 0.084 ;
  END
END INV_x8

MACRO MAJ_x1
  CLASS CORE ;
  ORIGIN 0 0 ;
  FOREIGN MAJ_x1 0 0 ;
  SIZE 0.336 BY 0.094 ;
  SYMMETRY X Y ;
  SITE CoreSite ;
  PIN A
    DIRECTION INPUT ;
    USE SIGNAL ;
    PORT
      LAYER M1 ;
        RECT 0.224 0.0125 0.238 0.0545 ;
    END
  END A
  PIN B
    DIRECTION INPUT ;
    USE SIGNAL ;
    PORT
      LAYER M1 ;
        RECT 0.098 0.0395 0.112 0.0815 ;
    END
  END B
  PIN C
    DIRECTION INPUT ;
    USE SIGNAL ;
    PORT
      LAYER M1 ;
        RECT 0.056 0.0165 0.07 0.0585 ;
    END
  END C
  PIN Y
    DIRECTION OUTPUT ;
    USE SIGNAL ;
    PORT
      LAYER M1 ;
        RECT 0.308 0.0185 0.322 0.0605 ;
    END
  END Y
  PIN VDD
    DIRECTION INOUT ;
    USE POWER ;
    SHAPE ABUTMENT ;
    PORT
      LAYER BSM0 ;
        RECT 0 0.062 0.336 0.126 ;
    END
  END VDD
  PIN VSS
    DIRECTION INOUT ;
    USE GROUND ;
    SHAPE ABUTMENT ;
    PORT
      LAYER BSM0 ;
        RECT 0 -0.032 0.336 0.032 ;
    END
  END VSS
  OBS
    LAYER M0 ;
      RECT 0.284 0.031 0.325 0.042 ;
      RECT 0.179 0.052 0.311 0.063 ;
      RECT 0.053 0.073 0.255 0.084 ;
      RECT 0.053 0.01 0.241 0.021 ;
      RECT 0.2 0.031 0.241 0.042 ;
      RECT 0.032 0.031 0.178 0.042 ;
      RECT 0.074 0.052 0.143 0.063 ;
  END
  PROPERTY pkpIndependentSourceSHA256 "c6524f313f9f278eef24616a36d5740bf9d2db56e62a49f5a092eda3790d412a" ;
END MAJ_x1

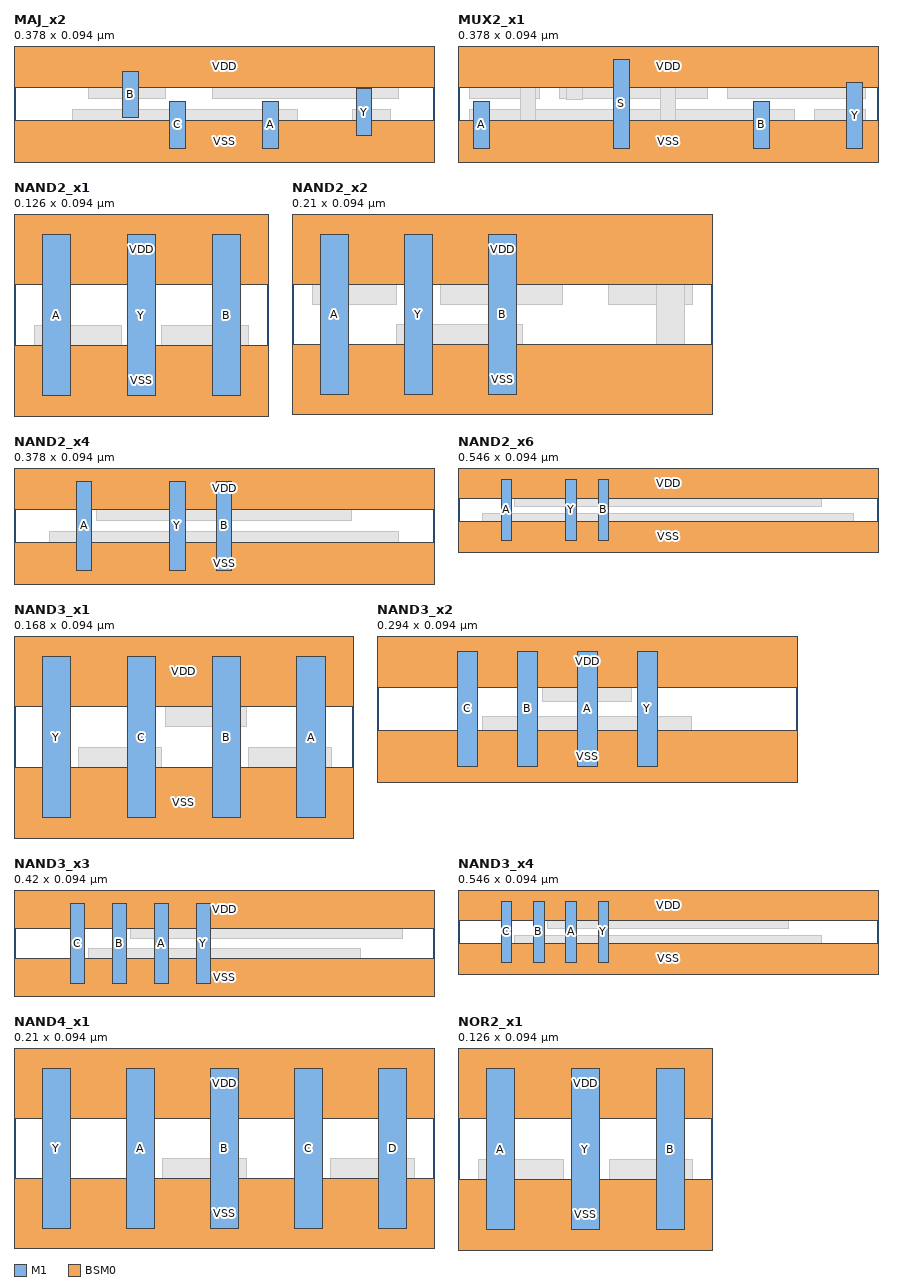
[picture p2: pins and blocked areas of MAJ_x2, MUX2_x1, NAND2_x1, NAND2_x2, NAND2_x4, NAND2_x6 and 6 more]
MACRO MAJ_x2
  CLASS CORE ;
  ORIGIN 0 0 ;
  FOREIGN MAJ_x2 0 0 ;
  SIZE 0.378 BY 0.094 ;
  SYMMETRY X Y ;
  SITE CoreSite ;
  PIN A
    DIRECTION INPUT ;
    USE SIGNAL ;
    PORT
      LAYER M1 ;
        RECT 0.224 0.007 0.238 0.049 ;
    END
  END A
  PIN B
    DIRECTION INPUT ;
    USE SIGNAL ;
    PORT
      LAYER M1 ;
        RECT 0.098 0.0345 0.112 0.0765 ;
    END
  END B
  PIN C
    DIRECTION INPUT ;
    USE SIGNAL ;
    PORT
      LAYER M1 ;
        RECT 0.14 0.007 0.154 0.049 ;
    END
  END C
  PIN Y
    DIRECTION OUTPUT ;
    USE SIGNAL ;
    PORT
      LAYER M1 ;
        RECT 0.308 0.0185 0.322 0.0605 ;
    END
  END Y
  PIN VDD
    DIRECTION INOUT ;
    USE POWER ;
    SHAPE ABUTMENT ;
    PORT
      LAYER BSM0 ;
        RECT 0 0.062 0.378 0.126 ;
    END
  END VDD
  PIN VSS
    DIRECTION INOUT ;
    USE GROUND ;
    SHAPE ABUTMENT ;
    PORT
      LAYER BSM0 ;
        RECT 0 -0.032 0.378 0.032 ;
    END
  END VSS
  OBS
    LAYER M0 ;
      RECT 0.179 0.052 0.346 0.063 ;
      RECT 0.305 0.031 0.339 0.042 ;
      RECT 0.053 0.031 0.255 0.042 ;
      RECT 0.2 0.01 0.241 0.021 ;
      RECT 0.053 0.073 0.241 0.084 ;
      RECT 0.032 0.01 0.178 0.021 ;
      RECT 0.067 0.052 0.136 0.063 ;
  END
  PROPERTY pkpIndependentSourceSHA256 "503b818806f41a63dad2466f29618c257b77dd42f9f3fecf4337ea01a5ae6336" ;
END MAJ_x2

MACRO MUX2_x1
  CLASS CORE ;
  ORIGIN 0 0 ;
  FOREIGN MUX2_x1 0 0 ;
  SIZE 0.378 BY 0.094 ;
  SYMMETRY X Y ;
  SITE CoreSite ;
  PIN A
    DIRECTION INPUT ;
    USE SIGNAL ;
    PORT
      LAYER M1 ;
        RECT 0.014 0.007 0.028 0.049 ;
    END
  END A
  PIN B
    DIRECTION INPUT ;
    USE SIGNAL ;
    PORT
      LAYER M1 ;
        RECT 0.266 0.007 0.28 0.049 ;
    END
  END B
  PIN S
    DIRECTION INPUT ;
    USE SIGNAL ;
    PORT
      LAYER M1 ;
        RECT 0.14 0.007 0.154 0.087 ;
    END
  END S
  PIN Y
    DIRECTION OUTPUT ;
    USE SIGNAL ;
    PORT
      LAYER M1 ;
        RECT 0.35 0.007 0.364 0.066 ;
    END
  END Y
  PIN VDD
    DIRECTION INOUT ;
    USE POWER ;
    SHAPE ABUTMENT ;
    PORT
      LAYER BSM0 ;
        RECT 0 0.062 0.378 0.126 ;
    END
  END VDD
  PIN VSS
    DIRECTION INOUT ;
    USE GROUND ;
    SHAPE ABUTMENT ;
    PORT
      LAYER BSM0 ;
        RECT 0 -0.032 0.378 0.032 ;
    END
  END VSS
  OBS
    LAYER M0 ;
      RECT 0.321 0.031 0.367 0.042 ;
      RECT 0.2425 0.052 0.367 0.063 ;
      RECT 0.174 0.073 0.346 0.084 ;
      RECT 0.243 0.01 0.3035 0.021 ;
      RECT 0.01 0.031 0.303 0.042 ;
      RECT 0.175 0.01 0.225 0.021 ;
      RECT 0.091 0.052 0.2245 0.063 ;
      RECT 0.111 0.01 0.157 0.021 ;
      RECT 0.033 0.073 0.156 0.084 ;
      RECT 0.01 0.01 0.093 0.021 ;
      RECT 0.01 0.052 0.073 0.063 ;
    LAYER M1 ;
      RECT 0.182 0.007 0.196 0.087 ;
      RECT 0.098 0.051 0.112 0.087 ;
      RECT 0.056 0.007 0.07 0.066 ;
  END
END MUX2_x1

MACRO NAND2_x1
  CLASS CORE ;
  ORIGIN 0 0 ;
  FOREIGN NAND2_x1 0 0 ;
  SIZE 0.126 BY 0.094 ;
  SYMMETRY X Y ;
  SITE CoreSite ;
  PIN A
    DIRECTION INPUT ;
    USE SIGNAL ;
    PORT
      LAYER M1 ;
        RECT 0.014 0.007 0.028 0.087 ;
    END
  END A
  PIN B
    DIRECTION INPUT ;
    USE SIGNAL ;
    PORT
      LAYER M1 ;
        RECT 0.098 0.007 0.112 0.087 ;
    END
  END B
  PIN Y
    DIRECTION OUTPUT ;
    USE SIGNAL ;
    PORT
      LAYER M1 ;
        RECT 0.056 0.007 0.07 0.087 ;
    END
  END Y
  PIN VDD
    DIRECTION INOUT ;
    USE POWER ;
    SHAPE ABUTMENT ;
    PORT
      LAYER BSM0 ;
        RECT 0 0.062 0.126 0.126 ;
    END
  END VDD
  PIN VSS
    DIRECTION INOUT ;
    USE GROUND ;
    SHAPE ABUTMENT ;
    PORT
      LAYER BSM0 ;
        RECT 0 -0.032 0.126 0.032 ;
    END
  END VSS
  OBS
    LAYER M0 ;
      RECT 0.052 0.01 0.116 0.021 ;
      RECT 0.073 0.031 0.116 0.042 ;
      RECT 0.01 0.073 0.116 0.084 ;
      RECT 0.01 0.031 0.053 0.042 ;
  END
END NAND2_x1

MACRO NAND2_x2
  CLASS CORE ;
  ORIGIN 0 0 ;
  FOREIGN NAND2_x2 0 0 ;
  SIZE 0.21 BY 0.094 ;
  SYMMETRY X Y ;
  SITE CoreSite ;
  PIN A
    DIRECTION INPUT ;
    USE SIGNAL ;
    PORT
      LAYER M1 ;
        RECT 0.014 0.007 0.028 0.087 ;
    END
  END A
  PIN B
    DIRECTION INPUT ;
    USE SIGNAL ;
    PORT
      LAYER M1 ;
        RECT 0.098 0.007 0.112 0.087 ;
    END
  END B
  PIN Y
    DIRECTION OUTPUT ;
    USE SIGNAL ;
    PORT
      LAYER M1 ;
        RECT 0.056 0.007 0.07 0.087 ;
    END
  END Y
  PIN VDD
    DIRECTION INOUT ;
    USE POWER ;
    SHAPE ABUTMENT ;
    PORT
      LAYER BSM0 ;
        RECT 0 0.062 0.21 0.126 ;
    END
  END VDD
  PIN VSS
    DIRECTION INOUT ;
    USE GROUND ;
    SHAPE ABUTMENT ;
    PORT
      LAYER BSM0 ;
        RECT 0 -0.032 0.21 0.032 ;
    END
  END VSS
  OBS
    LAYER M0 ;
      RECT 0.01 0.01 0.2 0.021 ;
      RECT 0.158 0.052 0.2 0.063 ;
      RECT 0.01 0.073 0.199 0.084 ;
      RECT 0.074 0.052 0.135 0.063 ;
      RECT 0.052 0.031 0.115 0.042 ;
      RECT 0.01 0.052 0.052 0.063 ;
    LAYER M1 ;
      RECT 0.182 0.007 0.196 0.087 ;
  END
END NAND2_x2

MACRO NAND2_x4
  CLASS CORE ;
  ORIGIN 0 0 ;
  FOREIGN NAND2_x4 0 0 ;
  SIZE 0.378 BY 0.094 ;
  SYMMETRY X Y ;
  SITE CoreSite ;
  PIN A
    DIRECTION INPUT ;
    USE SIGNAL ;
    PORT
      LAYER M1 ;
        RECT 0.056 0.007 0.07 0.087 ;
    END
  END A
  PIN B
    DIRECTION INPUT ;
    USE SIGNAL ;
    PORT
      LAYER M1 ;
        RECT 0.182 0.007 0.196 0.087 ;
    END
  END B
  PIN Y
    DIRECTION OUTPUT ;
    USE SIGNAL ;
    PORT
      LAYER M1 ;
        RECT 0.14 0.007 0.154 0.087 ;
    END
  END Y
  PIN VDD
    DIRECTION INOUT ;
    USE POWER ;
    SHAPE ABUTMENT ;
    PORT
      LAYER BSM0 ;
        RECT 0 0.062 0.378 0.126 ;
    END
  END VDD
  PIN VSS
    DIRECTION INOUT ;
    USE GROUND ;
    SHAPE ABUTMENT ;
    PORT
      LAYER BSM0 ;
        RECT 0 -0.032 0.378 0.032 ;
    END
  END VSS
  OBS
    LAYER M0 ;
      RECT 0.01 0.073 0.368 0.084 ;
      RECT 0.032 0.031 0.346 0.042 ;
      RECT 0.074 0.052 0.304 0.063 ;
      RECT 0.094 0.01 0.284 0.021 ;
  END
END NAND2_x4

MACRO NAND2_x6
  CLASS CORE ;
  ORIGIN 0 0 ;
  FOREIGN NAND2_x6 0 0 ;
  SIZE 0.546 BY 0.094 ;
  SYMMETRY X Y ;
  SITE CoreSite ;
  PIN A
    DIRECTION INPUT ;
    USE SIGNAL ;
    PORT
      LAYER M1 ;
        RECT 0.056 0.007 0.07 0.087 ;
    END
  END A
  PIN B
    DIRECTION INPUT ;
    USE SIGNAL ;
    PORT
      LAYER M1 ;
        RECT 0.182 0.007 0.196 0.087 ;
    END
  END B
  PIN Y
    DIRECTION OUTPUT ;
    USE SIGNAL ;
    PORT
      LAYER M1 ;
        RECT 0.14 0.007 0.154 0.087 ;
    END
  END Y
  PIN VDD
    DIRECTION INOUT ;
    USE POWER ;
    SHAPE ABUTMENT ;
    PORT
      LAYER BSM0 ;
        RECT 0 0.062 0.546 0.126 ;
    END
  END VDD
  PIN VSS
    DIRECTION INOUT ;
    USE GROUND ;
    SHAPE ABUTMENT ;
    PORT
      LAYER BSM0 ;
        RECT 0 -0.032 0.546 0.032 ;
    END
  END VSS
  OBS
    LAYER M0 ;
      RECT 0.01 0.073 0.536 0.084 ;
      RECT 0.032 0.031 0.514 0.042 ;
      RECT 0.074 0.052 0.472 0.063 ;
      RECT 0.094 0.01 0.452 0.021 ;
  END
END NAND2_x6

MACRO NAND3_x1
  CLASS CORE ;
  ORIGIN 0 0 ;
  FOREIGN NAND3_x1 0 0 ;
  SIZE 0.168 BY 0.094 ;
  SYMMETRY X Y ;
  SITE CoreSite ;
  PIN A
    DIRECTION INPUT ;
    USE SIGNAL ;
    PORT
      LAYER M1 ;
        RECT 0.14 0.007 0.154 0.087 ;
    END
  END A
  PIN B
    DIRECTION INPUT ;
    USE SIGNAL ;
    PORT
      LAYER M1 ;
        RECT 0.098 0.007 0.112 0.087 ;
    END
  END B
  PIN C
    DIRECTION INPUT ;
    USE SIGNAL ;
    PORT
      LAYER M1 ;
        RECT 0.056 0.007 0.07 0.087 ;
    END
  END C
  PIN Y
    DIRECTION OUTPUT ;
    USE SIGNAL ;
    PORT
      LAYER M1 ;
        RECT 0.014 0.007 0.028 0.087 ;
    END
  END Y
  PIN VDD
    DIRECTION INOUT ;
    USE POWER ;
    SHAPE ABUTMENT ;
    PORT
      LAYER BSM0 ;
        RECT 0 0.062 0.168 0.126 ;
    END
  END VDD
  PIN VSS
    DIRECTION INOUT ;
    USE GROUND ;
    SHAPE ABUTMENT ;
    PORT
      LAYER BSM0 ;
        RECT 0 -0.032 0.168 0.032 ;
    END
  END VSS
  OBS
    LAYER M0 ;
      RECT 0.116 0.031 0.157 0.042 ;
      RECT 0.075 0.052 0.115 0.063 ;
      RECT 0.01 0.073 0.114 0.084 ;
      RECT 0.032 0.031 0.073 0.042 ;
  END
END NAND3_x1

MACRO NAND3_x2
  CLASS CORE ;
  ORIGIN 0 0 ;
  FOREIGN NAND3_x2 0 0 ;
  SIZE 0.294 BY 0.094 ;
  SYMMETRY X Y ;
  SITE CoreSite ;
  PIN A
    DIRECTION INPUT ;
    USE SIGNAL ;
    PORT
      LAYER M1 ;
        RECT 0.14 0.007 0.154 0.087 ;
    END
  END A
  PIN B
    DIRECTION INPUT ;
    USE SIGNAL ;
    PORT
      LAYER M1 ;
        RECT 0.098 0.007 0.112 0.087 ;
    END
  END B
  PIN C
    DIRECTION INPUT ;
    USE SIGNAL ;
    PORT
      LAYER M1 ;
        RECT 0.056 0.007 0.07 0.087 ;
    END
  END C
  PIN Y
    DIRECTION OUTPUT ;
    USE SIGNAL ;
    PORT
      LAYER M1 ;
        RECT 0.182 0.007 0.196 0.087 ;
    END
  END Y
  PIN VDD
    DIRECTION INOUT ;
    USE POWER ;
    SHAPE ABUTMENT ;
    PORT
      LAYER BSM0 ;
        RECT 0 0.062 0.294 0.126 ;
    END
  END VDD
  PIN VSS
    DIRECTION INOUT ;
    USE GROUND ;
    SHAPE ABUTMENT ;
    PORT
      LAYER BSM0 ;
        RECT 0 -0.032 0.294 0.032 ;
    END
  END VSS
  OBS
    LAYER M0 ;
      RECT 0.01 0.073 0.284 0.084 ;
      RECT 0.032 0.01 0.262 0.021 ;
      RECT 0.074 0.031 0.22 0.042 ;
      RECT 0.116 0.052 0.178 0.063 ;
  END
END NAND3_x2

MACRO NAND3_x3
  CLASS CORE ;
  ORIGIN 0 0 ;
  FOREIGN NAND3_x3 0 0 ;
  SIZE 0.42 BY 0.094 ;
  SYMMETRY X Y ;
  SITE CoreSite ;
  PIN A
    DIRECTION INPUT ;
    USE SIGNAL ;
    PORT
      LAYER M1 ;
        RECT 0.14 0.007 0.154 0.087 ;
    END
  END A
  PIN B
    DIRECTION INPUT ;
    USE SIGNAL ;
    PORT
      LAYER M1 ;
        RECT 0.098 0.007 0.112 0.087 ;
    END
  END B
  PIN C
    DIRECTION INPUT ;
    USE SIGNAL ;
    PORT
      LAYER M1 ;
        RECT 0.056 0.007 0.07 0.087 ;
    END
  END C
  PIN Y
    DIRECTION OUTPUT ;
    USE SIGNAL ;
    PORT
      LAYER M1 ;
        RECT 0.182 0.007 0.196 0.087 ;
    END
  END Y
  PIN VDD
    DIRECTION INOUT ;
    USE POWER ;
    SHAPE ABUTMENT ;
    PORT
      LAYER BSM0 ;
        RECT 0 0.062 0.42 0.126 ;
    END
  END VDD
  PIN VSS
    DIRECTION INOUT ;
    USE GROUND ;
    SHAPE ABUTMENT ;
    PORT
      LAYER BSM0 ;
        RECT 0 -0.032 0.42 0.032 ;
    END
  END VSS
  OBS
    LAYER M0 ;
      RECT 0.01 0.073 0.41 0.084 ;
      RECT 0.116 0.052 0.388 0.063 ;
      RECT 0.074 0.031 0.346 0.042 ;
      RECT 0.032 0.01 0.304 0.021 ;
  END
END NAND3_x3

MACRO NAND3_x4
  CLASS CORE ;
  ORIGIN 0 0 ;
  FOREIGN NAND3_x4 0 0 ;
  SIZE 0.546 BY 0.094 ;
  SYMMETRY X Y ;
  SITE CoreSite ;
  PIN A
    DIRECTION INPUT ;
    USE SIGNAL ;
    PORT
      LAYER M1 ;
        RECT 0.14 0.007 0.154 0.087 ;
    END
  END A
  PIN B
    DIRECTION INPUT ;
    USE SIGNAL ;
    PORT
      LAYER M1 ;
        RECT 0.098 0.007 0.112 0.087 ;
    END
  END B
  PIN C
    DIRECTION INPUT ;
    USE SIGNAL ;
    PORT
      LAYER M1 ;
        RECT 0.056 0.007 0.07 0.087 ;
    END
  END C
  PIN Y
    DIRECTION OUTPUT ;
    USE SIGNAL ;
    PORT
      LAYER M1 ;
        RECT 0.182 0.007 0.196 0.087 ;
    END
  END Y
  PIN VDD
    DIRECTION INOUT ;
    USE POWER ;
    SHAPE ABUTMENT ;
    PORT
      LAYER BSM0 ;
        RECT 0 0.062 0.546 0.126 ;
    END
  END VDD
  PIN VSS
    DIRECTION INOUT ;
    USE GROUND ;
    SHAPE ABUTMENT ;
    PORT
      LAYER BSM0 ;
        RECT 0 -0.032 0.546 0.032 ;
    END
  END VSS
  OBS
    LAYER M0 ;
      RECT 0.01 0.073 0.536 0.084 ;
      RECT 0.032 0.01 0.514 0.021 ;
      RECT 0.074 0.031 0.472 0.042 ;
      RECT 0.116 0.052 0.43 0.063 ;
  END
END NAND3_x4

MACRO NAND4_x1
  CLASS CORE ;
  ORIGIN 0 0 ;
  FOREIGN NAND4_x1 0 0 ;
  SIZE 0.21 BY 0.094 ;
  SYMMETRY X Y ;
  SITE CoreSite ;
  PIN A
    DIRECTION INPUT ;
    USE SIGNAL ;
    PORT
      LAYER M1 ;
        RECT 0.056 0.007 0.07 0.087 ;
    END
  END A
  PIN B
    DIRECTION INPUT ;
    USE SIGNAL ;
    PORT
      LAYER M1 ;
        RECT 0.098 0.007 0.112 0.087 ;
    END
  END B
  PIN C
    DIRECTION INPUT ;
    USE SIGNAL ;
    PORT
      LAYER M1 ;
        RECT 0.14 0.007 0.154 0.087 ;
    END
  END C
  PIN D
    DIRECTION INPUT ;
    USE SIGNAL ;
    PORT
      LAYER M1 ;
        RECT 0.182 0.007 0.196 0.087 ;
    END
  END D
  PIN Y
    DIRECTION OUTPUT ;
    USE SIGNAL ;
    PORT
      LAYER M1 ;
        RECT 0.014 0.007 0.028 0.087 ;
    END
  END Y
  PIN VDD
    DIRECTION INOUT ;
    USE POWER ;
    SHAPE ABUTMENT ;
    PORT
      LAYER BSM0 ;
        RECT 0 0.062 0.21 0.126 ;
    END
  END VDD
  PIN VSS
    DIRECTION INOUT ;
    USE GROUND ;
    SHAPE ABUTMENT ;
    PORT
      LAYER BSM0 ;
        RECT 0 -0.032 0.21 0.032 ;
    END
  END VSS
  OBS
    LAYER M0 ;
      RECT 0.158 0.031 0.2 0.042 ;
      RECT 0.01 0.073 0.2 0.084 ;
      RECT 0.116 0.01 0.158 0.021 ;
      RECT 0.074 0.031 0.116 0.042 ;
      RECT 0.032 0.01 0.074 0.021 ;
  END
END NAND4_x1

MACRO NOR2_x1
  CLASS CORE ;
  ORIGIN 0 0 ;
  FOREIGN NOR2_x1 0 0 ;
  SIZE 0.126 BY 0.094 ;
  SYMMETRY X Y ;
  SITE CoreSite ;
  PIN A
    DIRECTION INPUT ;
    USE SIGNAL ;
    PORT
      LAYER M1 ;
        RECT 0.014 0.007 0.028 0.087 ;
    END
  END A
  PIN B
    DIRECTION INPUT ;
    USE SIGNAL ;
    PORT
      LAYER M1 ;
        RECT 0.098 0.007 0.112 0.087 ;
    END
  END B
  PIN Y
    DIRECTION OUTPUT ;
    USE SIGNAL ;
    PORT
      LAYER M1 ;
        RECT 0.056 0.007 0.07 0.087 ;
    END
  END Y
  PIN VDD
    DIRECTION INOUT ;
    USE POWER ;
    SHAPE ABUTMENT ;
    PORT
      LAYER BSM0 ;
        RECT 0 0.062 0.126 0.126 ;
    END
  END VDD
  PIN VSS
    DIRECTION INOUT ;
    USE GROUND ;
    SHAPE ABUTMENT ;
    PORT
      LAYER BSM0 ;
        RECT 0 -0.032 0.126 0.032 ;
    END
  END VSS
  OBS
    LAYER M0 ;
      RECT 0.01 0.01 0.116 0.021 ;
      RECT 0.075 0.031 0.116 0.042 ;
      RECT 0.052 0.073 0.116 0.084 ;
      RECT 0.01 0.031 0.052 0.042 ;
  END
END NOR2_x1

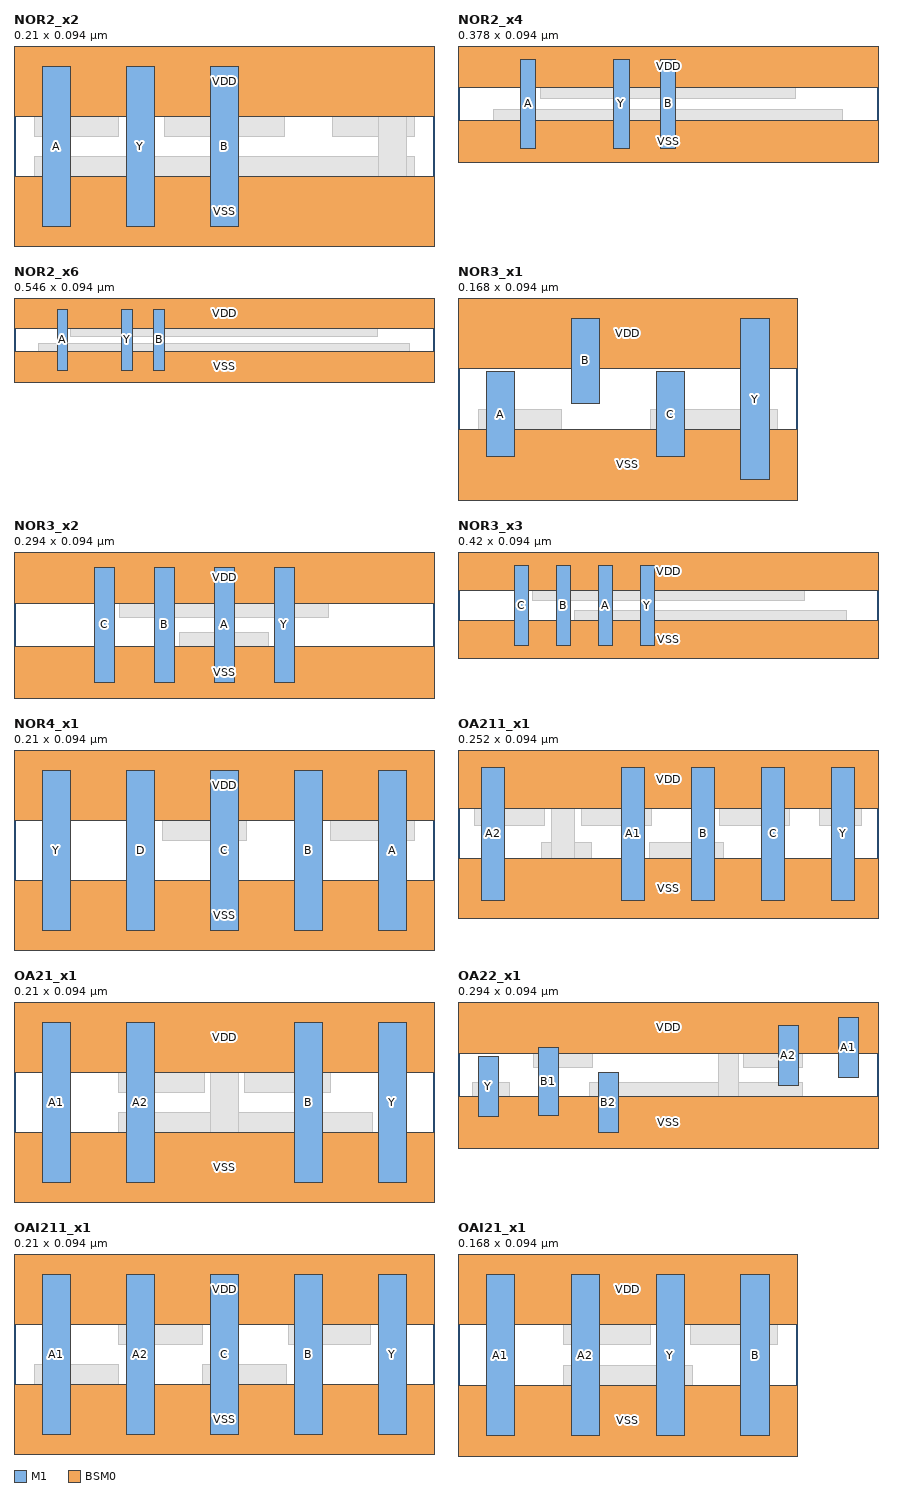
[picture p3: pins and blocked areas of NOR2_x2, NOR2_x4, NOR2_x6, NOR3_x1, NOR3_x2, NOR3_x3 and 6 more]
MACRO NOR2_x2
  CLASS CORE ;
  ORIGIN 0 0 ;
  FOREIGN NOR2_x2 0 0 ;
  SIZE 0.21 BY 0.094 ;
  SYMMETRY X Y ;
  SITE CoreSite ;
  PIN A
    DIRECTION INPUT ;
    USE SIGNAL ;
    PORT
      LAYER M1 ;
        RECT 0.014 0.007 0.028 0.087 ;
    END
  END A
  PIN B
    DIRECTION INPUT ;
    USE SIGNAL ;
    PORT
      LAYER M1 ;
        RECT 0.098 0.007 0.112 0.087 ;
    END
  END B
  PIN Y
    DIRECTION OUTPUT ;
    USE SIGNAL ;
    PORT
      LAYER M1 ;
        RECT 0.056 0.007 0.07 0.087 ;
    END
  END Y
  PIN VDD
    DIRECTION INOUT ;
    USE POWER ;
    SHAPE ABUTMENT ;
    PORT
      LAYER BSM0 ;
        RECT 0 0.062 0.21 0.126 ;
    END
  END VDD
  PIN VSS
    DIRECTION INOUT ;
    USE GROUND ;
    SHAPE ABUTMENT ;
    PORT
      LAYER BSM0 ;
        RECT 0 -0.032 0.21 0.032 ;
    END
  END VSS
  OBS
    LAYER M0 ;
      RECT 0.01 0.01 0.2 0.021 ;
      RECT 0.01 0.031 0.2 0.042 ;
      RECT 0.159 0.052 0.2 0.063 ;
      RECT 0.075 0.052 0.135 0.063 ;
      RECT 0.052 0.073 0.116 0.084 ;
      RECT 0.01 0.052 0.052 0.063 ;
    LAYER M1 ;
      RECT 0.182 0.007 0.196 0.087 ;
  END
END NOR2_x2

MACRO NOR2_x4
  CLASS CORE ;
  ORIGIN 0 0 ;
  FOREIGN NOR2_x4 0 0 ;
  SIZE 0.378 BY 0.094 ;
  SYMMETRY X Y ;
  SITE CoreSite ;
  PIN A
    DIRECTION INPUT ;
    USE SIGNAL ;
    PORT
      LAYER M1 ;
        RECT 0.056 0.007 0.07 0.087 ;
    END
  END A
  PIN B
    DIRECTION INPUT ;
    USE SIGNAL ;
    PORT
      LAYER M1 ;
        RECT 0.182 0.007 0.196 0.087 ;
    END
  END B
  PIN Y
    DIRECTION OUTPUT ;
    USE SIGNAL ;
    PORT
      LAYER M1 ;
        RECT 0.14 0.007 0.154 0.087 ;
    END
  END Y
  PIN VDD
    DIRECTION INOUT ;
    USE POWER ;
    SHAPE ABUTMENT ;
    PORT
      LAYER BSM0 ;
        RECT 0 0.062 0.378 0.126 ;
    END
  END VDD
  PIN VSS
    DIRECTION INOUT ;
    USE GROUND ;
    SHAPE ABUTMENT ;
    PORT
      LAYER BSM0 ;
        RECT 0 -0.032 0.378 0.032 ;
    END
  END VSS
  OBS
    LAYER M0 ;
      RECT 0.01 0.01 0.368 0.021 ;
      RECT 0.032 0.031 0.346 0.042 ;
      RECT 0.074 0.052 0.304 0.063 ;
      RECT 0.094 0.073 0.284 0.084 ;
  END
END NOR2_x4

MACRO NOR2_x6
  CLASS CORE ;
  ORIGIN 0 0 ;
  FOREIGN NOR2_x6 0 0 ;
  SIZE 0.546 BY 0.094 ;
  SYMMETRY X Y ;
  SITE CoreSite ;
  PIN A
    DIRECTION INPUT ;
    USE SIGNAL ;
    PORT
      LAYER M1 ;
        RECT 0.056 0.007 0.07 0.087 ;
    END
  END A
  PIN B
    DIRECTION INPUT ;
    USE SIGNAL ;
    PORT
      LAYER M1 ;
        RECT 0.182 0.007 0.196 0.087 ;
    END
  END B
  PIN Y
    DIRECTION OUTPUT ;
    USE SIGNAL ;
    PORT
      LAYER M1 ;
        RECT 0.14 0.007 0.154 0.087 ;
    END
  END Y
  PIN VDD
    DIRECTION INOUT ;
    USE POWER ;
    SHAPE ABUTMENT ;
    PORT
      LAYER BSM0 ;
        RECT 0 0.062 0.546 0.126 ;
    END
  END VDD
  PIN VSS
    DIRECTION INOUT ;
    USE GROUND ;
    SHAPE ABUTMENT ;
    PORT
      LAYER BSM0 ;
        RECT 0 -0.032 0.546 0.032 ;
    END
  END VSS
  OBS
    LAYER M0 ;
      RECT 0.01 0.01 0.536 0.021 ;
      RECT 0.032 0.031 0.514 0.042 ;
      RECT 0.074 0.052 0.472 0.063 ;
      RECT 0.094 0.073 0.452 0.084 ;
  END
END NOR2_x6

MACRO NOR3_x1
  CLASS CORE ;
  ORIGIN 0 0 ;
  FOREIGN NOR3_x1 0 0 ;
  SIZE 0.168 BY 0.094 ;
  SYMMETRY X Y ;
  SITE CoreSite ;
  PIN A
    DIRECTION INPUT ;
    USE SIGNAL ;
    PORT
      LAYER M1 ;
        RECT 0.014 0.0185 0.028 0.0605 ;
    END
  END A
  PIN B
    DIRECTION INPUT ;
    USE SIGNAL ;
    PORT
      LAYER M1 ;
        RECT 0.056 0.045 0.07 0.087 ;
    END
  END B
  PIN C
    DIRECTION INPUT ;
    USE SIGNAL ;
    PORT
      LAYER M1 ;
        RECT 0.098 0.0185 0.112 0.0605 ;
    END
  END C
  PIN Y
    DIRECTION OUTPUT ;
    USE SIGNAL ;
    PORT
      LAYER M1 ;
        RECT 0.14 0.007 0.154 0.087 ;
    END
  END Y
  PIN VDD
    DIRECTION INOUT ;
    USE POWER ;
    SHAPE ABUTMENT ;
    PORT
      LAYER BSM0 ;
        RECT 0 0.062 0.168 0.126 ;
    END
  END VDD
  PIN VSS
    DIRECTION INOUT ;
    USE GROUND ;
    SHAPE ABUTMENT ;
    PORT
      LAYER BSM0 ;
        RECT 0 -0.032 0.168 0.032 ;
    END
  END VSS
  OBS
    LAYER M0 ;
      RECT 0.095 0.031 0.158 0.042 ;
      RECT 0.012 0.01 0.157 0.021 ;
      RECT 0.116 0.073 0.157 0.084 ;
      RECT 0.053 0.073 0.0965 0.084 ;
      RECT 0.01 0.031 0.051 0.042 ;
  END
END NOR3_x1

MACRO NOR3_x2
  CLASS CORE ;
  ORIGIN 0 0 ;
  FOREIGN NOR3_x2 0 0 ;
  SIZE 0.294 BY 0.094 ;
  SYMMETRY X Y ;
  SITE CoreSite ;
  PIN A
    DIRECTION INPUT ;
    USE SIGNAL ;
    PORT
      LAYER M1 ;
        RECT 0.14 0.007 0.154 0.087 ;
    END
  END A
  PIN B
    DIRECTION INPUT ;
    USE SIGNAL ;
    PORT
      LAYER M1 ;
        RECT 0.098 0.007 0.112 0.087 ;
    END
  END B
  PIN C
    DIRECTION INPUT ;
    USE SIGNAL ;
    PORT
      LAYER M1 ;
        RECT 0.056 0.007 0.07 0.087 ;
    END
  END C
  PIN Y
    DIRECTION OUTPUT ;
    USE SIGNAL ;
    PORT
      LAYER M1 ;
        RECT 0.182 0.007 0.196 0.087 ;
    END
  END Y
  PIN VDD
    DIRECTION INOUT ;
    USE POWER ;
    SHAPE ABUTMENT ;
    PORT
      LAYER BSM0 ;
        RECT 0 0.062 0.294 0.126 ;
    END
  END VDD
  PIN VSS
    DIRECTION INOUT ;
    USE GROUND ;
    SHAPE ABUTMENT ;
    PORT
      LAYER BSM0 ;
        RECT 0 -0.032 0.294 0.032 ;
    END
  END VSS
  OBS
    LAYER M0 ;
      RECT 0.01 0.01 0.284 0.021 ;
      RECT 0.032 0.073 0.262 0.084 ;
      RECT 0.074 0.052 0.22 0.063 ;
      RECT 0.116 0.031 0.178 0.042 ;
  END
END NOR3_x2

MACRO NOR3_x3
  CLASS CORE ;
  ORIGIN 0 0 ;
  FOREIGN NOR3_x3 0 0 ;
  SIZE 0.42 BY 0.094 ;
  SYMMETRY X Y ;
  SITE CoreSite ;
  PIN A
    DIRECTION INPUT ;
    USE SIGNAL ;
    PORT
      LAYER M1 ;
        RECT 0.14 0.007 0.154 0.087 ;
    END
  END A
  PIN B
    DIRECTION INPUT ;
    USE SIGNAL ;
    PORT
      LAYER M1 ;
        RECT 0.098 0.007 0.112 0.087 ;
    END
  END B
  PIN C
    DIRECTION INPUT ;
    USE SIGNAL ;
    PORT
      LAYER M1 ;
        RECT 0.056 0.007 0.07 0.087 ;
    END
  END C
  PIN Y
    DIRECTION OUTPUT ;
    USE SIGNAL ;
    PORT
      LAYER M1 ;
        RECT 0.182 0.007 0.196 0.087 ;
    END
  END Y
  PIN VDD
    DIRECTION INOUT ;
    USE POWER ;
    SHAPE ABUTMENT ;
    PORT
      LAYER BSM0 ;
        RECT 0 0.062 0.42 0.126 ;
    END
  END VDD
  PIN VSS
    DIRECTION INOUT ;
    USE GROUND ;
    SHAPE ABUTMENT ;
    PORT
      LAYER BSM0 ;
        RECT 0 -0.032 0.42 0.032 ;
    END
  END VSS
  OBS
    LAYER M0 ;
      RECT 0.01 0.01 0.41 0.021 ;
      RECT 0.116 0.031 0.388 0.042 ;
      RECT 0.074 0.052 0.346 0.063 ;
      RECT 0.032 0.073 0.304 0.084 ;
  END
END NOR3_x3

MACRO NOR4_x1
  CLASS CORE ;
  ORIGIN 0 0 ;
  FOREIGN NOR4_x1 0 0 ;
  SIZE 0.21 BY 0.094 ;
  SYMMETRY X Y ;
  SITE CoreSite ;
  PIN A
    DIRECTION INPUT ;
    USE SIGNAL ;
    PORT
      LAYER M1 ;
        RECT 0.182 0.007 0.196 0.087 ;
    END
  END A
  PIN B
    DIRECTION INPUT ;
    USE SIGNAL ;
    PORT
      LAYER M1 ;
        RECT 0.14 0.007 0.154 0.087 ;
    END
  END B
  PIN C
    DIRECTION INPUT ;
    USE SIGNAL ;
    PORT
      LAYER M1 ;
        RECT 0.098 0.007 0.112 0.087 ;
    END
  END C
  PIN D
    DIRECTION INPUT ;
    USE SIGNAL ;
    PORT
      LAYER M1 ;
        RECT 0.056 0.007 0.07 0.087 ;
    END
  END D
  PIN Y
    DIRECTION OUTPUT ;
    USE SIGNAL ;
    PORT
      LAYER M1 ;
        RECT 0.014 0.007 0.028 0.087 ;
    END
  END Y
  PIN VDD
    DIRECTION INOUT ;
    USE POWER ;
    SHAPE ABUTMENT ;
    PORT
      LAYER BSM0 ;
        RECT 0 0.062 0.21 0.126 ;
    END
  END VDD
  PIN VSS
    DIRECTION INOUT ;
    USE GROUND ;
    SHAPE ABUTMENT ;
    PORT
      LAYER BSM0 ;
        RECT 0 -0.032 0.21 0.032 ;
    END
  END VSS
  OBS
    LAYER M0 ;
      RECT 0.01 0.01 0.2 0.021 ;
      RECT 0.158 0.052 0.2 0.063 ;
      RECT 0.116 0.073 0.158 0.084 ;
      RECT 0.074 0.052 0.116 0.063 ;
      RECT 0.032 0.073 0.074 0.084 ;
  END
END NOR4_x1

MACRO OA211_x1
  CLASS CORE ;
  ORIGIN 0 0 ;
  FOREIGN OA211_x1 0 0 ;
  SIZE 0.252 BY 0.094 ;
  SYMMETRY X Y ;
  SITE CoreSite ;
  PIN A1
    DIRECTION INPUT ;
    USE SIGNAL ;
    PORT
      LAYER M1 ;
        RECT 0.098 0.007 0.112 0.087 ;
    END
  END A1
  PIN A2
    DIRECTION INPUT ;
    USE SIGNAL ;
    PORT
      LAYER M1 ;
        RECT 0.014 0.007 0.028 0.087 ;
    END
  END A2
  PIN B
    DIRECTION INPUT ;
    USE SIGNAL ;
    PORT
      LAYER M1 ;
        RECT 0.14 0.007 0.154 0.087 ;
    END
  END B
  PIN C
    DIRECTION INPUT ;
    USE SIGNAL ;
    PORT
      LAYER M1 ;
        RECT 0.182 0.007 0.196 0.087 ;
    END
  END C
  PIN Y
    DIRECTION OUTPUT ;
    USE SIGNAL ;
    PORT
      LAYER M1 ;
        RECT 0.224 0.007 0.238 0.087 ;
    END
  END Y
  PIN VDD
    DIRECTION INOUT ;
    USE POWER ;
    SHAPE ABUTMENT ;
    PORT
      LAYER BSM0 ;
        RECT 0 0.062 0.252 0.126 ;
    END
  END VDD
  PIN VSS
    DIRECTION INOUT ;
    USE GROUND ;
    SHAPE ABUTMENT ;
    PORT
      LAYER BSM0 ;
        RECT 0 -0.032 0.252 0.032 ;
    END
  END VSS
  OBS
    LAYER M0 ;
      RECT 0.217 0.01 0.242 0.021 ;
      RECT 0.217 0.052 0.242 0.063 ;
      RECT 0.01 0.073 0.221 0.084 ;
      RECT 0.157 0.052 0.199 0.063 ;
      RECT 0.115 0.031 0.159 0.042 ;
      RECT 0.01 0.01 0.117 0.021 ;
      RECT 0.074 0.052 0.116 0.063 ;
      RECT 0.05 0.031 0.08 0.042 ;
      RECT 0.01 0.052 0.052 0.063 ;
    LAYER M1 ;
      RECT 0.056 0.007 0.07 0.087 ;
  END
END OA211_x1

MACRO OA21_x1
  CLASS CORE ;
  ORIGIN 0 0 ;
  FOREIGN OA21_x1 0 0 ;
  SIZE 0.21 BY 0.094 ;
  SYMMETRY X Y ;
  SITE CoreSite ;
  PIN A1
    DIRECTION INPUT ;
    USE SIGNAL ;
    PORT
      LAYER M1 ;
        RECT 0.014 0.007 0.028 0.087 ;
    END
  END A1
  PIN A2
    DIRECTION INPUT ;
    USE SIGNAL ;
    PORT
      LAYER M1 ;
        RECT 0.056 0.007 0.07 0.087 ;
    END
  END A2
  PIN B
    DIRECTION INPUT ;
    USE SIGNAL ;
    PORT
      LAYER M1 ;
        RECT 0.14 0.007 0.154 0.087 ;
    END
  END B
  PIN Y
    DIRECTION OUTPUT ;
    USE SIGNAL ;
    PORT
      LAYER M1 ;
        RECT 0.182 0.007 0.196 0.087 ;
    END
  END Y
  PIN VDD
    DIRECTION INOUT ;
    USE POWER ;
    SHAPE ABUTMENT ;
    PORT
      LAYER BSM0 ;
        RECT 0 0.062 0.21 0.126 ;
    END
  END VDD
  PIN VSS
    DIRECTION INOUT ;
    USE GROUND ;
    SHAPE ABUTMENT ;
    PORT
      LAYER BSM0 ;
        RECT 0 -0.032 0.21 0.032 ;
    END
  END VSS
  OBS
    LAYER M0 ;
      RECT 0.172 0.01 0.2 0.021 ;
      RECT 0.172 0.073 0.2 0.084 ;
      RECT 0.052 0.031 0.179 0.042 ;
      RECT 0.115 0.052 0.158 0.063 ;
      RECT 0.088 0.073 0.118 0.084 ;
      RECT 0.01 0.01 0.116 0.021 ;
      RECT 0.052 0.052 0.095 0.063 ;
      RECT 0.01 0.073 0.053 0.084 ;
    LAYER M1 ;
      RECT 0.098 0.007 0.112 0.087 ;
  END
END OA21_x1

MACRO OA22_x1
  CLASS CORE ;
  ORIGIN 0 0 ;
  FOREIGN OA22_x1 0 0 ;
  SIZE 0.294 BY 0.094 ;
  SYMMETRY X Y ;
  SITE CoreSite ;
  PIN A1
    DIRECTION INPUT ;
    USE SIGNAL ;
    PORT
      LAYER M1 ;
        RECT 0.266 0.045 0.28 0.087 ;
    END
  END A1
  PIN A2
    DIRECTION INPUT ;
    USE SIGNAL ;
    PORT
      LAYER M1 ;
        RECT 0.224 0.0395 0.238 0.0815 ;
    END
  END A2
  PIN B1
    DIRECTION INPUT ;
    USE SIGNAL ;
    PORT
      LAYER M1 ;
        RECT 0.056 0.0185 0.07 0.066 ;
    END
  END B1
  PIN B2
    DIRECTION INPUT ;
    USE SIGNAL ;
    PORT
      LAYER M1 ;
        RECT 0.098 0.007 0.112 0.049 ;
    END
  END B2
  PIN Y
    DIRECTION OUTPUT ;
    USE SIGNAL ;
    PORT
      LAYER M1 ;
        RECT 0.014 0.018 0.028 0.06 ;
    END
  END Y
  PIN VDD
    DIRECTION INOUT ;
    USE POWER ;
    SHAPE ABUTMENT ;
    PORT
      LAYER BSM0 ;
        RECT 0 0.062 0.294 0.126 ;
    END
  END VDD
  PIN VSS
    DIRECTION INOUT ;
    USE GROUND ;
    SHAPE ABUTMENT ;
    PORT
      LAYER BSM0 ;
        RECT 0 -0.032 0.294 0.032 ;
    END
  END VSS
  OBS
    LAYER M0 ;
      RECT 0.172 0.01 0.284 0.021 ;
      RECT 0.242 0.073 0.283 0.084 ;
      RECT 0.092 0.031 0.241 0.042 ;
      RECT 0.2 0.052 0.241 0.063 ;
      RECT 0.032 0.073 0.202 0.084 ;
      RECT 0.095 0.01 0.143 0.021 ;
      RECT 0.053 0.052 0.094 0.063 ;
      RECT 0.01 0.031 0.036 0.042 ;
    LAYER M1 ;
      RECT 0.182 0.007 0.196 0.087 ;
  END
  PROPERTY CatenaDesignType "deviceLevel" ;
  PROPERTY pkpIndependentSourceSHA256 "c547a8aa444d608dc216510e46f1f0709ec88807917adefe6256126d9f2918d8" ;
END OA22_x1

MACRO OAI211_x1
  CLASS CORE ;
  ORIGIN 0 0 ;
  FOREIGN OAI211_x1 0 0 ;
  SIZE 0.21 BY 0.094 ;
  SYMMETRY X Y ;
  SITE CoreSite ;
  PIN A1
    DIRECTION INPUT ;
    USE SIGNAL ;
    PORT
      LAYER M1 ;
        RECT 0.014 0.007 0.028 0.087 ;
    END
  END A1
  PIN A2
    DIRECTION INPUT ;
    USE SIGNAL ;
    PORT
      LAYER M1 ;
        RECT 0.056 0.007 0.07 0.087 ;
    END
  END A2
  PIN B
    DIRECTION INPUT ;
    USE SIGNAL ;
    PORT
      LAYER M1 ;
        RECT 0.14 0.007 0.154 0.087 ;
    END
  END B
  PIN C
    DIRECTION INPUT ;
    USE SIGNAL ;
    PORT
      LAYER M1 ;
        RECT 0.098 0.007 0.112 0.087 ;
    END
  END C
  PIN Y
    DIRECTION OUTPUT ;
    USE SIGNAL ;
    PORT
      LAYER M1 ;
        RECT 0.182 0.007 0.196 0.087 ;
    END
  END Y
  PIN VDD
    DIRECTION INOUT ;
    USE POWER ;
    SHAPE ABUTMENT ;
    PORT
      LAYER BSM0 ;
        RECT 0 0.062 0.21 0.126 ;
    END
  END VDD
  PIN VSS
    DIRECTION INOUT ;
    USE GROUND ;
    SHAPE ABUTMENT ;
    PORT
      LAYER BSM0 ;
        RECT 0 -0.032 0.21 0.032 ;
    END
  END VSS
  OBS
    LAYER M0 ;
      RECT 0.172 0.01 0.2 0.021 ;
      RECT 0.093 0.073 0.2 0.084 ;
      RECT 0.137 0.052 0.178 0.063 ;
      RECT 0.094 0.031 0.136 0.042 ;
      RECT 0.011 0.01 0.115 0.021 ;
      RECT 0.052 0.052 0.094 0.063 ;
      RECT 0.01 0.031 0.052 0.042 ;
  END
END OAI211_x1

MACRO OAI21_x1
  CLASS CORE ;
  ORIGIN 0 0 ;
  FOREIGN OAI21_x1 0 0 ;
  SIZE 0.168 BY 0.094 ;
  SYMMETRY X Y ;
  SITE CoreSite ;
  PIN A1
    DIRECTION INPUT ;
    USE SIGNAL ;
    PORT
      LAYER M1 ;
        RECT 0.014 0.007 0.028 0.087 ;
    END
  END A1
  PIN A2
    DIRECTION INPUT ;
    USE SIGNAL ;
    PORT
      LAYER M1 ;
        RECT 0.056 0.007 0.07 0.087 ;
    END
  END A2
  PIN B
    DIRECTION INPUT ;
    USE SIGNAL ;
    PORT
      LAYER M1 ;
        RECT 0.14 0.007 0.154 0.087 ;
    END
  END B
  PIN Y
    DIRECTION OUTPUT ;
    USE SIGNAL ;
    PORT
      LAYER M1 ;
        RECT 0.098 0.007 0.112 0.087 ;
    END
  END Y
  PIN VDD
    DIRECTION INOUT ;
    USE POWER ;
    SHAPE ABUTMENT ;
    PORT
      LAYER BSM0 ;
        RECT 0 0.062 0.168 0.126 ;
    END
  END VDD
  PIN VSS
    DIRECTION INOUT ;
    USE GROUND ;
    SHAPE ABUTMENT ;
    PORT
      LAYER BSM0 ;
        RECT 0 -0.032 0.168 0.032 ;
    END
  END VSS
  OBS
    LAYER M0 ;
      RECT 0.115 0.052 0.158 0.063 ;
      RECT 0.088 0.073 0.118 0.084 ;
      RECT 0.01 0.01 0.116 0.021 ;
      RECT 0.052 0.031 0.116 0.042 ;
      RECT 0.052 0.052 0.095 0.063 ;
      RECT 0.01 0.073 0.053 0.084 ;
  END
  PROPERTY CatenaDesignType "deviceLevel" ;
END OAI21_x1

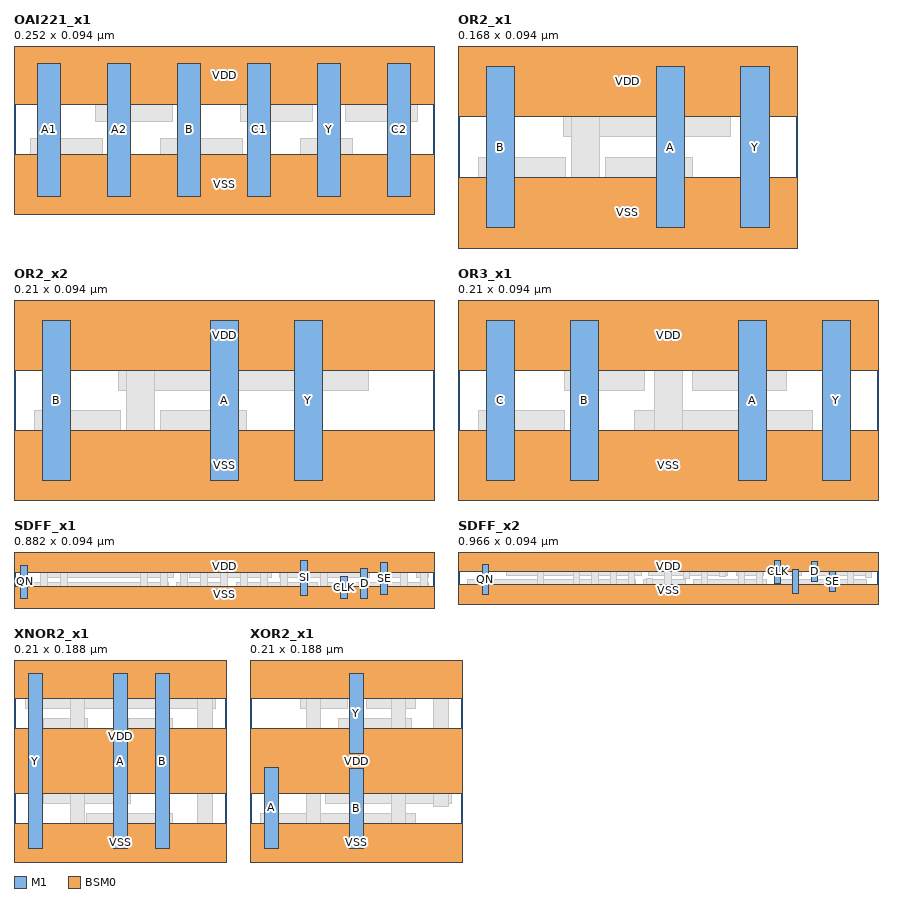
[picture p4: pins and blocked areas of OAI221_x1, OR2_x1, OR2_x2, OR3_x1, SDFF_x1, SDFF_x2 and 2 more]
MACRO OAI221_x1
  CLASS CORE ;
  ORIGIN 0 0 ;
  FOREIGN OAI221_x1 0 0 ;
  SIZE 0.252 BY 0.094 ;
  SYMMETRY X Y ;
  SITE CoreSite ;
  PIN A1
    DIRECTION INPUT ;
    USE SIGNAL ;
    PORT
      LAYER M1 ;
        RECT 0.014 0.007 0.028 0.087 ;
    END
  END A1
  PIN A2
    DIRECTION INPUT ;
    USE SIGNAL ;
    PORT
      LAYER M1 ;
        RECT 0.056 0.007 0.07 0.087 ;
    END
  END A2
  PIN B
    DIRECTION INPUT ;
    USE SIGNAL ;
    PORT
      LAYER M1 ;
        RECT 0.098 0.007 0.112 0.087 ;
    END
  END B
  PIN C1
    DIRECTION INPUT ;
    USE SIGNAL ;
    PORT
      LAYER M1 ;
        RECT 0.14 0.007 0.154 0.087 ;
    END
  END C1
  PIN C2
    DIRECTION INPUT ;
    USE SIGNAL ;
    PORT
      LAYER M1 ;
        RECT 0.224 0.007 0.238 0.087 ;
    END
  END C2
  PIN Y
    DIRECTION OUTPUT ;
    USE SIGNAL ;
    PORT
      LAYER M1 ;
        RECT 0.182 0.007 0.196 0.087 ;
    END
  END Y
  PIN VDD
    DIRECTION INOUT ;
    USE POWER ;
    SHAPE ABUTMENT ;
    PORT
      LAYER BSM0 ;
        RECT 0 0.062 0.252 0.126 ;
    END
  END VDD
  PIN VSS
    DIRECTION INOUT ;
    USE GROUND ;
    SHAPE ABUTMENT ;
    PORT
      LAYER BSM0 ;
        RECT 0 -0.032 0.252 0.032 ;
    END
  END VSS
  OBS
    LAYER M0 ;
      RECT 0.137 0.01 0.242 0.021 ;
      RECT 0.199 0.052 0.242 0.063 ;
      RECT 0.094 0.073 0.242 0.084 ;
      RECT 0.172 0.031 0.203 0.042 ;
      RECT 0.136 0.052 0.179 0.063 ;
      RECT 0.088 0.031 0.137 0.042 ;
      RECT 0.01 0.01 0.115 0.021 ;
      RECT 0.049 0.052 0.095 0.063 ;
      RECT 0.01 0.031 0.053 0.042 ;
  END
END OAI221_x1

MACRO OR2_x1
  CLASS CORE ;
  ORIGIN 0 0 ;
  FOREIGN OR2_x1 0 0 ;
  SIZE 0.168 BY 0.094 ;
  SYMMETRY X Y ;
  SITE CoreSite ;
  PIN A
    DIRECTION INPUT ;
    USE SIGNAL ;
    PORT
      LAYER M1 ;
        RECT 0.098 0.007 0.112 0.087 ;
    END
  END A
  PIN B
    DIRECTION INPUT ;
    USE SIGNAL ;
    PORT
      LAYER M1 ;
        RECT 0.014 0.007 0.028 0.087 ;
    END
  END B
  PIN Y
    DIRECTION OUTPUT ;
    USE SIGNAL ;
    PORT
      LAYER M1 ;
        RECT 0.14 0.007 0.154 0.087 ;
    END
  END Y
  PIN VDD
    DIRECTION INOUT ;
    USE POWER ;
    SHAPE ABUTMENT ;
    PORT
      LAYER BSM0 ;
        RECT 0 0.062 0.168 0.126 ;
    END
  END VDD
  PIN VSS
    DIRECTION INOUT ;
    USE GROUND ;
    SHAPE ABUTMENT ;
    PORT
      LAYER BSM0 ;
        RECT 0 -0.032 0.168 0.032 ;
    END
  END VSS
  OBS
    LAYER M0 ;
      RECT 0.133 0.01 0.158 0.021 ;
      RECT 0.133 0.073 0.158 0.084 ;
      RECT 0.052 0.052 0.135 0.063 ;
      RECT 0.073 0.031 0.116 0.042 ;
      RECT 0.05 0.01 0.08 0.021 ;
      RECT 0.01 0.073 0.08 0.084 ;
      RECT 0.01 0.031 0.053 0.042 ;
    LAYER M1 ;
      RECT 0.056 0.007 0.07 0.087 ;
  END
END OR2_x1

MACRO OR2_x2
  CLASS CORE ;
  ORIGIN 0 0 ;
  FOREIGN OR2_x2 0 0 ;
  SIZE 0.21 BY 0.094 ;
  SYMMETRY X Y ;
  SITE CoreSite ;
  PIN A
    DIRECTION INPUT ;
    USE SIGNAL ;
    PORT
      LAYER M1 ;
        RECT 0.098 0.007 0.112 0.087 ;
    END
  END A
  PIN B
    DIRECTION INPUT ;
    USE SIGNAL ;
    PORT
      LAYER M1 ;
        RECT 0.014 0.007 0.028 0.087 ;
    END
  END B
  PIN Y
    DIRECTION OUTPUT ;
    USE SIGNAL ;
    PORT
      LAYER M1 ;
        RECT 0.14 0.007 0.154 0.087 ;
    END
  END Y
  PIN VDD
    DIRECTION INOUT ;
    USE POWER ;
    SHAPE ABUTMENT ;
    PORT
      LAYER BSM0 ;
        RECT 0 0.062 0.21 0.126 ;
    END
  END VDD
  PIN VSS
    DIRECTION INOUT ;
    USE GROUND ;
    SHAPE ABUTMENT ;
    PORT
      LAYER BSM0 ;
        RECT 0 -0.032 0.21 0.032 ;
    END
  END VSS
  OBS
    LAYER M0 ;
      RECT 0.052 0.052 0.177 0.063 ;
      RECT 0.134 0.01 0.164 0.021 ;
      RECT 0.134 0.073 0.164 0.084 ;
      RECT 0.073 0.031 0.116 0.042 ;
      RECT 0.05 0.01 0.08 0.021 ;
      RECT 0.01 0.073 0.08 0.084 ;
      RECT 0.01 0.031 0.053 0.042 ;
    LAYER M1 ;
      RECT 0.056 0.007 0.07 0.087 ;
  END
END OR2_x2

MACRO OR3_x1
  CLASS CORE ;
  ORIGIN 0 0 ;
  FOREIGN OR3_x1 0 0 ;
  SIZE 0.21 BY 0.094 ;
  SYMMETRY X Y ;
  SITE CoreSite ;
  PIN A
    DIRECTION INPUT ;
    USE SIGNAL ;
    PORT
      LAYER M1 ;
        RECT 0.14 0.007 0.154 0.087 ;
    END
  END A
  PIN B
    DIRECTION INPUT ;
    USE SIGNAL ;
    PORT
      LAYER M1 ;
        RECT 0.056 0.007 0.07 0.087 ;
    END
  END B
  PIN C
    DIRECTION INPUT ;
    USE SIGNAL ;
    PORT
      LAYER M1 ;
        RECT 0.014 0.007 0.028 0.087 ;
    END
  END C
  PIN Y
    DIRECTION OUTPUT ;
    USE SIGNAL ;
    PORT
      LAYER M1 ;
        RECT 0.182 0.007 0.196 0.087 ;
    END
  END Y
  PIN VDD
    DIRECTION INOUT ;
    USE POWER ;
    SHAPE ABUTMENT ;
    PORT
      LAYER BSM0 ;
        RECT 0 0.062 0.21 0.126 ;
    END
  END VDD
  PIN VSS
    DIRECTION INOUT ;
    USE GROUND ;
    SHAPE ABUTMENT ;
    PORT
      LAYER BSM0 ;
        RECT 0 -0.032 0.21 0.032 ;
    END
  END VSS
  OBS
    LAYER M0 ;
      RECT 0.172 0.01 0.2 0.021 ;
      RECT 0.172 0.073 0.2 0.084 ;
      RECT 0.088 0.031 0.177 0.042 ;
      RECT 0.117 0.052 0.164 0.063 ;
      RECT 0.011 0.01 0.118 0.021 ;
      RECT 0.01 0.073 0.118 0.084 ;
      RECT 0.053 0.052 0.093 0.063 ;
      RECT 0.01 0.031 0.053 0.042 ;
    LAYER M1 ;
      RECT 0.098 0.007 0.112 0.087 ;
  END
END OR3_x1

MACRO SDFF_x1
  CLASS CORE ;
  ORIGIN 0 0 ;
  FOREIGN SDFF_x1 0 0 ;
  SIZE 0.882 BY 0.094 ;
  SYMMETRY X Y ;
  SITE CoreSite ;
  PIN CLK
    DIRECTION INPUT ;
    USE CLOCK ;
    PORT
      LAYER M1 ;
        RECT 0.686 0.007 0.7 0.0545 ;
    END
  END CLK
  PIN D
    DIRECTION INPUT ;
    USE SIGNAL ;
    PORT
      LAYER M1 ;
        RECT 0.728 0.007 0.742 0.071 ;
    END
  END D
  PIN QN
    DIRECTION OUTPUT ;
    USE SIGNAL ;
    PORT
      LAYER M1 ;
        RECT 0.014 0.007 0.028 0.0775 ;
    END
  END QN
  PIN SE
    DIRECTION INPUT ;
    USE SIGNAL ;
    PORT
      LAYER M1 ;
        RECT 0.77 0.015 0.784 0.0835 ;
    END
  END SE
  PIN SI
    DIRECTION INPUT ;
    USE SIGNAL ;
    PORT
      LAYER M1 ;
        RECT 0.602 0.0145 0.616 0.087 ;
    END
  END SI
  PIN VDD
    DIRECTION INOUT ;
    USE POWER ;
    SHAPE ABUTMENT ;
    PORT
      LAYER BSM0 ;
        RECT 0 0.062 0.882 0.126 ;
    END
  END VDD
  PIN VSS
    DIRECTION INOUT ;
    USE GROUND ;
    SHAPE ABUTMENT ;
    PORT
      LAYER BSM0 ;
        RECT 0 -0.032 0.882 0.032 ;
    END
  END VSS
  OBS
    LAYER M0 ;
      RECT 0.789 0.01 0.872 0.021 ;
      RECT 0.6565 0.031 0.871 0.042 ;
      RECT 0.705 0.073 0.871 0.084 ;
      RECT 0.845 0.052 0.87 0.063 ;
      RECT 0.764 0.052 0.8145 0.063 ;
      RECT 0.725 0.01 0.7695 0.021 ;
      RECT 0.558 0.052 0.7455 0.063 ;
      RECT 0.615 0.01 0.707 0.021 ;
      RECT 0.5985 0.073 0.687 0.084 ;
      RECT 0.4665 0.031 0.638 0.042 ;
      RECT 0.305 0.01 0.591 0.021 ;
      RECT 0.537 0.073 0.5805 0.084 ;
      RECT 0.369 0.052 0.54 0.063 ;
      RECT 0.1345 0.073 0.519 0.084 ;
      RECT 0.342 0.031 0.4355 0.042 ;
      RECT 0.0645 0.052 0.334 0.063 ;
      RECT 0.016 0.031 0.324 0.042 ;
      RECT 0.242 0.01 0.286 0.021 ;
      RECT 0.094 0.01 0.2235 0.021 ;
      RECT 0.0915 0.073 0.1165 0.084 ;
      RECT 0.019 0.073 0.0735 0.084 ;
      RECT 0.01 0.01 0.06 0.021 ;
    LAYER M1 ;
      RECT 0.854 0.007 0.868 0.087 ;
      RECT 0.812 0.007 0.826 0.0835 ;
      RECT 0.644 0.0325 0.658 0.0855 ;
      RECT 0.56 0.007 0.574 0.087 ;
      RECT 0.518 0.012 0.532 0.087 ;
      RECT 0.476 0.0075 0.49 0.087 ;
      RECT 0.434 0.015 0.448 0.071 ;
      RECT 0.392 0.008 0.406 0.077 ;
      RECT 0.35 0.007 0.364 0.084 ;
      RECT 0.308 0.007 0.322 0.087 ;
      RECT 0.266 0.007 0.28 0.087 ;
      RECT 0.098 0.007 0.112 0.087 ;
      RECT 0.056 0.025 0.07 0.087 ;
  END
END SDFF_x1

MACRO SDFF_x2
  CLASS CORE ;
  ORIGIN 0 0 ;
  FOREIGN SDFF_x2 0 0 ;
  SIZE 0.966 BY 0.094 ;
  SYMMETRY X Y ;
  SITE CoreSite ;
  PIN CLK
    DIRECTION INPUT ;
    USE CLOCK ;
    PORT
      LAYER M1 ;
        RECT 0.728 0.034 0.742 0.087 ;
    END
  END CLK
  PIN D
    DIRECTION INPUT ;
    USE SIGNAL ;
    PORT
      LAYER M1 ;
        RECT 0.812 0.039 0.826 0.0835 ;
    END
  END D
  PIN QN
    DIRECTION OUTPUT ;
    USE SIGNAL ;
    PORT
      LAYER M1 ;
        RECT 0.056 0.007 0.07 0.0765 ;
    END
  END QN
  PIN SE
    DIRECTION INPUT ;
    USE SIGNAL ;
    PORT
      LAYER M1 ;
        RECT 0.854 0.0155 0.868 0.0605 ;
    END
  END SE
  PIN SI
    DIRECTION INPUT ;
    USE SIGNAL ;
    PORT
      LAYER M1 ;
        RECT 0.77 0.0105 0.784 0.066 ;
    END
  END SI
  PIN VDD
    DIRECTION INOUT ;
    USE POWER ;
    SHAPE ABUTMENT ;
    PORT
      LAYER BSM0 ;
        RECT 0 0.062 0.966 0.126 ;
    END
  END VDD
  PIN VSS
    DIRECTION INOUT ;
    USE GROUND ;
    SHAPE ABUTMENT ;
    PORT
      LAYER BSM0 ;
        RECT 0 -0.032 0.966 0.032 ;
    END
  END VSS
  OBS
    LAYER M0 ;
      RECT 0.7655 0.073 0.956 0.084 ;
      RECT 0.8675 0.01 0.9555 0.021 ;
      RECT 0.8705 0.052 0.939 0.063 ;
      RECT 0.728 0.031 0.9385 0.042 ;
      RECT 0.809 0.052 0.851 0.063 ;
      RECT 0.68 0.01 0.8395 0.021 ;
      RECT 0.7435 0.052 0.79 0.063 ;
      RECT 0.705 0.073 0.7455 0.084 ;
      RECT 0.5405 0.031 0.71 0.042 ;
      RECT 0.64 0.052 0.7035 0.063 ;
      RECT 0.6205 0.073 0.675 0.084 ;
      RECT 0.387 0.01 0.662 0.021 ;
      RECT 0.439 0.052 0.619 0.063 ;
      RECT 0.2425 0.073 0.6015 0.084 ;
      RECT 0.4265 0.031 0.5225 0.042 ;
      RECT 0.112 0.052 0.421 0.063 ;
      RECT 0.0225 0.031 0.408 0.042 ;
      RECT 0.324 0.01 0.369 0.021 ;
      RECT 0.1785 0.01 0.3055 0.021 ;
      RECT 0.031 0.073 0.2235 0.084 ;
      RECT 0.036 0.01 0.1505 0.021 ;
    LAYER M1 ;
      RECT 0.938 0.047 0.952 0.087 ;
      RECT 0.896 0.028 0.91 0.0755 ;
      RECT 0.686 0.007 0.7 0.0725 ;
      RECT 0.644 0.007 0.658 0.087 ;
      RECT 0.602 0.049 0.616 0.086 ;
      RECT 0.56 0.0135 0.574 0.087 ;
      RECT 0.518 0.044 0.532 0.087 ;
      RECT 0.476 0.02 0.49 0.087 ;
      RECT 0.434 0.009 0.448 0.046 ;
      RECT 0.392 0.007 0.406 0.0745 ;
      RECT 0.35 0.007 0.364 0.087 ;
      RECT 0.308 0.0305 0.322 0.087 ;
      RECT 0.266 0.007 0.28 0.0815 ;
      RECT 0.182 0.021 0.196 0.087 ;
  END
END SDFF_x2

MACRO XNOR2_x1
  CLASS CORE ;
  ORIGIN 0 0 ;
  FOREIGN XNOR2_x1 0 0 ;
  SIZE 0.21 BY 0.188 ;
  SYMMETRY X Y ;
  SITE CoreSite ;
  PIN A
    DIRECTION INPUT ;
    USE SIGNAL ;
    PORT
      LAYER M1 ;
        RECT 0.098 0.007 0.112 0.181 ;
    END
  END A
  PIN B
    DIRECTION INPUT ;
    USE SIGNAL ;
    PORT
      LAYER M1 ;
        RECT 0.14 0.007 0.154 0.181 ;
    END
  END B
  PIN Y
    DIRECTION OUTPUT ;
    USE SIGNAL ;
    PORT
      LAYER M1 ;
        RECT 0.014 0.007 0.028 0.181 ;
    END
  END Y
  PIN VDD
    DIRECTION INOUT ;
    USE POWER ;
    SHAPE ABUTMENT ;
    PORT
      LAYER BSM0 ;
        RECT 0 0.062 0.21 0.126 ;
    END
  END VDD
  PIN VSS
    DIRECTION INOUT ;
    USE GROUND ;
    SHAPE ABUTMENT ;
    PORT
      LAYER BSM0 ;
        RECT 0 -0.032 0.21 0.032 ;
        RECT 0 0.156 0.21 0.22 ;
    END
  END VSS
  OBS
    LAYER M0 ;
      RECT 0.1345 0.104 0.199 0.115 ;
      RECT 0.011 0.146 0.199 0.157 ;
      RECT 0.0715 0.031 0.157 0.042 ;
      RECT 0.1135 0.125 0.157 0.136 ;
      RECT 0.054 0.167 0.156 0.178 ;
      RECT 0.053 0.01 0.1175 0.021 ;
      RECT 0.0295 0.052 0.115 0.063 ;
      RECT 0.0715 0.104 0.115 0.115 ;
      RECT 0.012 0.073 0.114 0.084 ;
      RECT 0.0295 0.125 0.073 0.136 ;
      RECT 0.01 0.104 0.035 0.115 ;
    LAYER M1 ;
      RECT 0.182 0.007 0.196 0.181 ;
      RECT 0.056 0.007 0.07 0.181 ;
  END
END XNOR2_x1

MACRO XOR2_x1
  CLASS CORE ;
  ORIGIN 0 0 ;
  FOREIGN XOR2_x1 0 0 ;
  SIZE 0.21 BY 0.188 ;
  SYMMETRY X Y ;
  SITE CoreSite ;
  PIN A
    DIRECTION INPUT ;
    USE SIGNAL ;
    PORT
      LAYER M1 ;
        RECT 0.014 0.007 0.028 0.088 ;
    END
  END A
  PIN B
    DIRECTION INPUT ;
    USE SIGNAL ;
    PORT
      LAYER M1 ;
        RECT 0.098 0.007 0.112 0.087 ;
    END
  END B
  PIN Y
    DIRECTION OUTPUT ;
    USE SIGNAL ;
    PORT
      LAYER M1 ;
        RECT 0.098 0.101 0.112 0.181 ;
    END
  END Y
  PIN VDD
    DIRECTION INOUT ;
    USE POWER ;
    SHAPE ABUTMENT ;
    PORT
      LAYER BSM0 ;
        RECT 0 0.062 0.21 0.126 ;
    END
  END VDD
  PIN VSS
    DIRECTION INOUT ;
    USE GROUND ;
    SHAPE ABUTMENT ;
    PORT
      LAYER BSM0 ;
        RECT 0 -0.032 0.21 0.032 ;
        RECT 0 0.156 0.21 0.22 ;
    END
  END VSS
  OBS
    LAYER M0 ;
      RECT 0.092 0.104 0.2 0.115 ;
      RECT 0.158 0.167 0.2 0.178 ;
      RECT 0.075 0.052 0.199 0.063 ;
      RECT 0.01 0.031 0.164 0.042 ;
      RECT 0.115 0.146 0.164 0.157 ;
      RECT 0.088 0.125 0.16 0.136 ;
      RECT 0.088 0.167 0.118 0.178 ;
      RECT 0.01 0.01 0.116 0.021 ;
      RECT 0.052 0.073 0.116 0.084 ;
      RECT 0.05 0.146 0.096 0.157 ;
    LAYER M1 ;
      RECT 0.182 0.049 0.196 0.181 ;
      RECT 0.14 0.028 0.154 0.181 ;
      RECT 0.056 0.007 0.07 0.181 ;
  END
END XOR2_x1

END LIBRARY
